VERSION 5.8 ;
BUSBITCHARS "[]" ;
DIVIDERCHAR "/" ;
UNITS
    DATABASE MICRONS 1000 ;
END UNITS

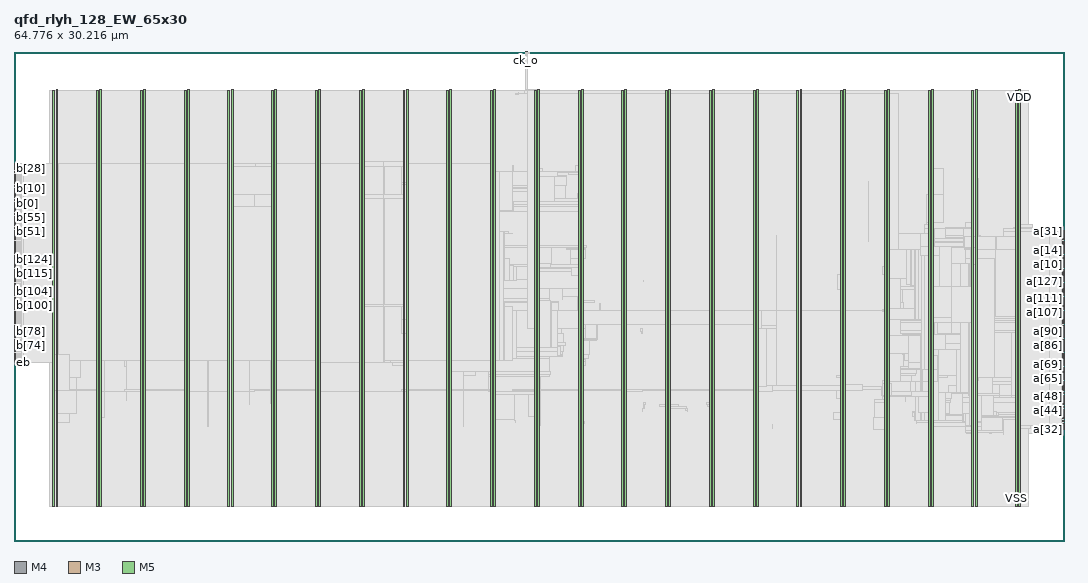
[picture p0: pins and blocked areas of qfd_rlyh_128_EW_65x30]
MACRO qfd_rlyh_128_EW_65x30
  FOREIGN qfd_rlyh_128_EW_65x30 0 0 ;
  CLASS BLOCK ;
  SIZE 64.776 BY 30.216 ;
  PIN a[0]
    DIRECTION INPUT ;
    USE SIGNAL ;
    PORT
      LAYER M4 ;
        RECT  64.692 16.08 64.776 16.104 ;
    END
  END a[0]
  PIN a[100]
    DIRECTION INPUT ;
    USE SIGNAL ;
    PORT
      LAYER M4 ;
        RECT  64.692 13.392 64.776 13.416 ;
    END
  END a[100]
  PIN a[101]
    DIRECTION INPUT ;
    USE SIGNAL ;
    PORT
      LAYER M4 ;
        RECT  64.692 13.488 64.776 13.512 ;
    END
  END a[101]
  PIN a[102]
    DIRECTION INPUT ;
    USE SIGNAL ;
    PORT
      LAYER M4 ;
        RECT  64.692 13.584 64.776 13.608 ;
    END
  END a[102]
  PIN a[103]
    DIRECTION INPUT ;
    USE SIGNAL ;
    PORT
      LAYER M4 ;
        RECT  64.692 13.68 64.776 13.704 ;
    END
  END a[103]
  PIN a[104]
    DIRECTION INPUT ;
    USE SIGNAL ;
    PORT
      LAYER M4 ;
        RECT  64.692 13.776 64.776 13.8 ;
    END
  END a[104]
  PIN a[105]
    DIRECTION INPUT ;
    USE SIGNAL ;
    PORT
      LAYER M4 ;
        RECT  64.692 13.872 64.776 13.896 ;
    END
  END a[105]
  PIN a[106]
    DIRECTION INPUT ;
    USE SIGNAL ;
    PORT
      LAYER M4 ;
        RECT  64.692 13.968 64.776 13.992 ;
    END
  END a[106]
  PIN a[107]
    DIRECTION INPUT ;
    USE SIGNAL ;
    PORT
      LAYER M4 ;
        RECT  64.692 14.064 64.776 14.088 ;
    END
  END a[107]
  PIN a[108]
    DIRECTION INPUT ;
    USE SIGNAL ;
    PORT
      LAYER M4 ;
        RECT  64.692 14.16 64.776 14.184 ;
    END
  END a[108]
  PIN a[109]
    DIRECTION INPUT ;
    USE SIGNAL ;
    PORT
      LAYER M4 ;
        RECT  64.692 14.256 64.776 14.28 ;
    END
  END a[109]
  PIN a[10]
    DIRECTION INPUT ;
    USE SIGNAL ;
    PORT
      LAYER M4 ;
        RECT  64.692 17.04 64.776 17.064 ;
    END
  END a[10]
  PIN a[110]
    DIRECTION INPUT ;
    USE SIGNAL ;
    PORT
      LAYER M4 ;
        RECT  64.692 14.352 64.776 14.376 ;
    END
  END a[110]
  PIN a[111]
    DIRECTION INPUT ;
    USE SIGNAL ;
    PORT
      LAYER M4 ;
        RECT  64.692 14.448 64.776 14.472 ;
    END
  END a[111]
  PIN a[112]
    DIRECTION INPUT ;
    USE SIGNAL ;
    PORT
      LAYER M4 ;
        RECT  64.692 14.544 64.776 14.568 ;
    END
  END a[112]
  PIN a[113]
    DIRECTION INPUT ;
    USE SIGNAL ;
    PORT
      LAYER M4 ;
        RECT  64.692 14.64 64.776 14.664 ;
    END
  END a[113]
  PIN a[114]
    DIRECTION INPUT ;
    USE SIGNAL ;
    PORT
      LAYER M4 ;
        RECT  64.692 14.736 64.776 14.76 ;
    END
  END a[114]
  PIN a[115]
    DIRECTION INPUT ;
    USE SIGNAL ;
    PORT
      LAYER M4 ;
        RECT  64.692 14.832 64.776 14.856 ;
    END
  END a[115]
  PIN a[116]
    DIRECTION INPUT ;
    USE SIGNAL ;
    PORT
      LAYER M4 ;
        RECT  64.692 14.928 64.776 14.952 ;
    END
  END a[116]
  PIN a[117]
    DIRECTION INPUT ;
    USE SIGNAL ;
    PORT
      LAYER M4 ;
        RECT  64.692 15.024 64.776 15.048 ;
    END
  END a[117]
  PIN a[118]
    DIRECTION INPUT ;
    USE SIGNAL ;
    PORT
      LAYER M4 ;
        RECT  64.692 15.12 64.776 15.144 ;
    END
  END a[118]
  PIN a[119]
    DIRECTION INPUT ;
    USE SIGNAL ;
    PORT
      LAYER M4 ;
        RECT  64.692 15.216 64.776 15.24 ;
    END
  END a[119]
  PIN a[11]
    DIRECTION INPUT ;
    USE SIGNAL ;
    PORT
      LAYER M4 ;
        RECT  64.692 17.136 64.776 17.16 ;
    END
  END a[11]
  PIN a[120]
    DIRECTION INPUT ;
    USE SIGNAL ;
    PORT
      LAYER M4 ;
        RECT  64.692 15.312 64.776 15.336 ;
    END
  END a[120]
  PIN a[121]
    DIRECTION INPUT ;
    USE SIGNAL ;
    PORT
      LAYER M4 ;
        RECT  64.692 15.408 64.776 15.432 ;
    END
  END a[121]
  PIN a[122]
    DIRECTION INPUT ;
    USE SIGNAL ;
    PORT
      LAYER M4 ;
        RECT  64.692 15.504 64.776 15.528 ;
    END
  END a[122]
  PIN a[123]
    DIRECTION INPUT ;
    USE SIGNAL ;
    PORT
      LAYER M4 ;
        RECT  64.692 15.6 64.776 15.624 ;
    END
  END a[123]
  PIN a[124]
    DIRECTION INPUT ;
    USE SIGNAL ;
    PORT
      LAYER M4 ;
        RECT  64.692 15.696 64.776 15.72 ;
    END
  END a[124]
  PIN a[125]
    DIRECTION INPUT ;
    USE SIGNAL ;
    PORT
      LAYER M4 ;
        RECT  64.692 15.792 64.776 15.816 ;
    END
  END a[125]
  PIN a[126]
    DIRECTION INPUT ;
    USE SIGNAL ;
    PORT
      LAYER M4 ;
        RECT  64.692 15.888 64.776 15.912 ;
    END
  END a[126]
  PIN a[127]
    DIRECTION INPUT ;
    USE SIGNAL ;
    PORT
      LAYER M4 ;
        RECT  64.692 15.984 64.776 16.008 ;
    END
  END a[127]
  PIN a[12]
    DIRECTION INPUT ;
    USE SIGNAL ;
    PORT
      LAYER M4 ;
        RECT  64.692 17.232 64.776 17.256 ;
    END
  END a[12]
  PIN a[13]
    DIRECTION INPUT ;
    USE SIGNAL ;
    PORT
      LAYER M4 ;
        RECT  64.692 17.328 64.776 17.352 ;
    END
  END a[13]
  PIN a[14]
    DIRECTION INPUT ;
    USE SIGNAL ;
    PORT
      LAYER M4 ;
        RECT  64.692 17.424 64.776 17.448 ;
    END
  END a[14]
  PIN a[15]
    DIRECTION INPUT ;
    USE SIGNAL ;
    PORT
      LAYER M4 ;
        RECT  64.692 17.52 64.776 17.544 ;
    END
  END a[15]
  PIN a[16]
    DIRECTION INPUT ;
    USE SIGNAL ;
    PORT
      LAYER M4 ;
        RECT  64.692 17.616 64.776 17.64 ;
    END
  END a[16]
  PIN a[17]
    DIRECTION INPUT ;
    USE SIGNAL ;
    PORT
      LAYER M4 ;
        RECT  64.692 17.712 64.776 17.736 ;
    END
  END a[17]
  PIN a[18]
    DIRECTION INPUT ;
    USE SIGNAL ;
    PORT
      LAYER M4 ;
        RECT  64.692 17.808 64.776 17.832 ;
    END
  END a[18]
  PIN a[19]
    DIRECTION INPUT ;
    USE SIGNAL ;
    PORT
      LAYER M4 ;
        RECT  64.692 17.904 64.776 17.928 ;
    END
  END a[19]
  PIN a[1]
    DIRECTION INPUT ;
    USE SIGNAL ;
    PORT
      LAYER M4 ;
        RECT  64.692 16.176 64.776 16.2 ;
    END
  END a[1]
  PIN a[20]
    DIRECTION INPUT ;
    USE SIGNAL ;
    PORT
      LAYER M4 ;
        RECT  64.692 18 64.776 18.024 ;
    END
  END a[20]
  PIN a[21]
    DIRECTION INPUT ;
    USE SIGNAL ;
    PORT
      LAYER M4 ;
        RECT  64.692 18.096 64.776 18.12 ;
    END
  END a[21]
  PIN a[22]
    DIRECTION INPUT ;
    USE SIGNAL ;
    PORT
      LAYER M4 ;
        RECT  64.692 18.192 64.776 18.216 ;
    END
  END a[22]
  PIN a[23]
    DIRECTION INPUT ;
    USE SIGNAL ;
    PORT
      LAYER M4 ;
        RECT  64.692 18.288 64.776 18.312 ;
    END
  END a[23]
  PIN a[24]
    DIRECTION INPUT ;
    USE SIGNAL ;
    PORT
      LAYER M4 ;
        RECT  64.692 18.384 64.776 18.408 ;
    END
  END a[24]
  PIN a[25]
    DIRECTION INPUT ;
    USE SIGNAL ;
    PORT
      LAYER M4 ;
        RECT  64.692 18.48 64.776 18.504 ;
    END
  END a[25]
  PIN a[26]
    DIRECTION INPUT ;
    USE SIGNAL ;
    PORT
      LAYER M4 ;
        RECT  64.692 18.576 64.776 18.6 ;
    END
  END a[26]
  PIN a[27]
    DIRECTION INPUT ;
    USE SIGNAL ;
    PORT
      LAYER M4 ;
        RECT  64.692 18.672 64.776 18.696 ;
    END
  END a[27]
  PIN a[28]
    DIRECTION INPUT ;
    USE SIGNAL ;
    PORT
      LAYER M4 ;
        RECT  64.692 18.768 64.776 18.792 ;
    END
  END a[28]
  PIN a[29]
    DIRECTION INPUT ;
    USE SIGNAL ;
    PORT
      LAYER M4 ;
        RECT  64.692 18.864 64.776 18.888 ;
    END
  END a[29]
  PIN a[2]
    DIRECTION INPUT ;
    USE SIGNAL ;
    PORT
      LAYER M4 ;
        RECT  64.692 16.272 64.776 16.296 ;
    END
  END a[2]
  PIN a[30]
    DIRECTION INPUT ;
    USE SIGNAL ;
    PORT
      LAYER M4 ;
        RECT  64.692 18.96 64.776 18.984 ;
    END
  END a[30]
  PIN a[31]
    DIRECTION INPUT ;
    USE SIGNAL ;
    PORT
      LAYER M4 ;
        RECT  64.692 19.056 64.776 19.08 ;
    END
  END a[31]
  PIN a[32]
    DIRECTION INPUT ;
    USE SIGNAL ;
    PORT
      LAYER M4 ;
        RECT  64.692 6.864 64.776 6.888 ;
    END
  END a[32]
  PIN a[33]
    DIRECTION INPUT ;
    USE SIGNAL ;
    PORT
      LAYER M4 ;
        RECT  64.692 6.96 64.776 6.984 ;
    END
  END a[33]
  PIN a[34]
    DIRECTION INPUT ;
    USE SIGNAL ;
    PORT
      LAYER M4 ;
        RECT  64.692 7.056 64.776 7.08 ;
    END
  END a[34]
  PIN a[35]
    DIRECTION INPUT ;
    USE SIGNAL ;
    PORT
      LAYER M4 ;
        RECT  64.692 7.152 64.776 7.176 ;
    END
  END a[35]
  PIN a[36]
    DIRECTION INPUT ;
    USE SIGNAL ;
    PORT
      LAYER M4 ;
        RECT  64.692 7.248 64.776 7.272 ;
    END
  END a[36]
  PIN a[37]
    DIRECTION INPUT ;
    USE SIGNAL ;
    PORT
      LAYER M4 ;
        RECT  64.692 7.344 64.776 7.368 ;
    END
  END a[37]
  PIN a[38]
    DIRECTION INPUT ;
    USE SIGNAL ;
    PORT
      LAYER M4 ;
        RECT  64.692 7.44 64.776 7.464 ;
    END
  END a[38]
  PIN a[39]
    DIRECTION INPUT ;
    USE SIGNAL ;
    PORT
      LAYER M4 ;
        RECT  64.692 7.536 64.776 7.56 ;
    END
  END a[39]
  PIN a[3]
    DIRECTION INPUT ;
    USE SIGNAL ;
    PORT
      LAYER M4 ;
        RECT  64.692 16.368 64.776 16.392 ;
    END
  END a[3]
  PIN a[40]
    DIRECTION INPUT ;
    USE SIGNAL ;
    PORT
      LAYER M4 ;
        RECT  64.692 7.632 64.776 7.656 ;
    END
  END a[40]
  PIN a[41]
    DIRECTION INPUT ;
    USE SIGNAL ;
    PORT
      LAYER M4 ;
        RECT  64.692 7.728 64.776 7.752 ;
    END
  END a[41]
  PIN a[42]
    DIRECTION INPUT ;
    USE SIGNAL ;
    PORT
      LAYER M4 ;
        RECT  64.692 7.824 64.776 7.848 ;
    END
  END a[42]
  PIN a[43]
    DIRECTION INPUT ;
    USE SIGNAL ;
    PORT
      LAYER M4 ;
        RECT  64.692 7.92 64.776 7.944 ;
    END
  END a[43]
  PIN a[44]
    DIRECTION INPUT ;
    USE SIGNAL ;
    PORT
      LAYER M4 ;
        RECT  64.692 8.016 64.776 8.04 ;
    END
  END a[44]
  PIN a[45]
    DIRECTION INPUT ;
    USE SIGNAL ;
    PORT
      LAYER M4 ;
        RECT  64.692 8.112 64.776 8.136 ;
    END
  END a[45]
  PIN a[46]
    DIRECTION INPUT ;
    USE SIGNAL ;
    PORT
      LAYER M4 ;
        RECT  64.692 8.208 64.776 8.232 ;
    END
  END a[46]
  PIN a[47]
    DIRECTION INPUT ;
    USE SIGNAL ;
    PORT
      LAYER M4 ;
        RECT  64.692 8.304 64.776 8.328 ;
    END
  END a[47]
  PIN a[48]
    DIRECTION INPUT ;
    USE SIGNAL ;
    PORT
      LAYER M4 ;
        RECT  64.692 8.4 64.776 8.424 ;
    END
  END a[48]
  PIN a[49]
    DIRECTION INPUT ;
    USE SIGNAL ;
    PORT
      LAYER M4 ;
        RECT  64.692 8.496 64.776 8.52 ;
    END
  END a[49]
  PIN a[4]
    DIRECTION INPUT ;
    USE SIGNAL ;
    PORT
      LAYER M4 ;
        RECT  64.692 16.464 64.776 16.488 ;
    END
  END a[4]
  PIN a[50]
    DIRECTION INPUT ;
    USE SIGNAL ;
    PORT
      LAYER M4 ;
        RECT  64.692 8.592 64.776 8.616 ;
    END
  END a[50]
  PIN a[51]
    DIRECTION INPUT ;
    USE SIGNAL ;
    PORT
      LAYER M4 ;
        RECT  64.692 8.688 64.776 8.712 ;
    END
  END a[51]
  PIN a[52]
    DIRECTION INPUT ;
    USE SIGNAL ;
    PORT
      LAYER M4 ;
        RECT  64.692 8.784 64.776 8.808 ;
    END
  END a[52]
  PIN a[53]
    DIRECTION INPUT ;
    USE SIGNAL ;
    PORT
      LAYER M4 ;
        RECT  64.692 8.88 64.776 8.904 ;
    END
  END a[53]
  PIN a[54]
    DIRECTION INPUT ;
    USE SIGNAL ;
    PORT
      LAYER M4 ;
        RECT  64.692 8.976 64.776 9 ;
    END
  END a[54]
  PIN a[55]
    DIRECTION INPUT ;
    USE SIGNAL ;
    PORT
      LAYER M4 ;
        RECT  64.692 9.072 64.776 9.096 ;
    END
  END a[55]
  PIN a[56]
    DIRECTION INPUT ;
    USE SIGNAL ;
    PORT
      LAYER M4 ;
        RECT  64.692 9.168 64.776 9.192 ;
    END
  END a[56]
  PIN a[57]
    DIRECTION INPUT ;
    USE SIGNAL ;
    PORT
      LAYER M4 ;
        RECT  64.692 9.264 64.776 9.288 ;
    END
  END a[57]
  PIN a[58]
    DIRECTION INPUT ;
    USE SIGNAL ;
    PORT
      LAYER M4 ;
        RECT  64.692 9.36 64.776 9.384 ;
    END
  END a[58]
  PIN a[59]
    DIRECTION INPUT ;
    USE SIGNAL ;
    PORT
      LAYER M4 ;
        RECT  64.692 9.456 64.776 9.48 ;
    END
  END a[59]
  PIN a[5]
    DIRECTION INPUT ;
    USE SIGNAL ;
    PORT
      LAYER M4 ;
        RECT  64.692 16.56 64.776 16.584 ;
    END
  END a[5]
  PIN a[60]
    DIRECTION INPUT ;
    USE SIGNAL ;
    PORT
      LAYER M4 ;
        RECT  64.692 9.552 64.776 9.576 ;
    END
  END a[60]
  PIN a[61]
    DIRECTION INPUT ;
    USE SIGNAL ;
    PORT
      LAYER M4 ;
        RECT  64.692 9.648 64.776 9.672 ;
    END
  END a[61]
  PIN a[62]
    DIRECTION INPUT ;
    USE SIGNAL ;
    PORT
      LAYER M4 ;
        RECT  64.692 9.744 64.776 9.768 ;
    END
  END a[62]
  PIN a[63]
    DIRECTION INPUT ;
    USE SIGNAL ;
    PORT
      LAYER M4 ;
        RECT  64.692 9.84 64.776 9.864 ;
    END
  END a[63]
  PIN a[64]
    DIRECTION INPUT ;
    USE SIGNAL ;
    PORT
      LAYER M4 ;
        RECT  64.692 9.936 64.776 9.96 ;
    END
  END a[64]
  PIN a[65]
    DIRECTION INPUT ;
    USE SIGNAL ;
    PORT
      LAYER M4 ;
        RECT  64.692 10.032 64.776 10.056 ;
    END
  END a[65]
  PIN a[66]
    DIRECTION INPUT ;
    USE SIGNAL ;
    PORT
      LAYER M4 ;
        RECT  64.692 10.128 64.776 10.152 ;
    END
  END a[66]
  PIN a[67]
    DIRECTION INPUT ;
    USE SIGNAL ;
    PORT
      LAYER M4 ;
        RECT  64.692 10.224 64.776 10.248 ;
    END
  END a[67]
  PIN a[68]
    DIRECTION INPUT ;
    USE SIGNAL ;
    PORT
      LAYER M4 ;
        RECT  64.692 10.32 64.776 10.344 ;
    END
  END a[68]
  PIN a[69]
    DIRECTION INPUT ;
    USE SIGNAL ;
    PORT
      LAYER M4 ;
        RECT  64.692 10.416 64.776 10.44 ;
    END
  END a[69]
  PIN a[6]
    DIRECTION INPUT ;
    USE SIGNAL ;
    PORT
      LAYER M4 ;
        RECT  64.692 16.656 64.776 16.68 ;
    END
  END a[6]
  PIN a[70]
    DIRECTION INPUT ;
    USE SIGNAL ;
    PORT
      LAYER M4 ;
        RECT  64.692 10.512 64.776 10.536 ;
    END
  END a[70]
  PIN a[71]
    DIRECTION INPUT ;
    USE SIGNAL ;
    PORT
      LAYER M4 ;
        RECT  64.692 10.608 64.776 10.632 ;
    END
  END a[71]
  PIN a[72]
    DIRECTION INPUT ;
    USE SIGNAL ;
    PORT
      LAYER M4 ;
        RECT  64.692 10.704 64.776 10.728 ;
    END
  END a[72]
  PIN a[73]
    DIRECTION INPUT ;
    USE SIGNAL ;
    PORT
      LAYER M4 ;
        RECT  64.692 10.8 64.776 10.824 ;
    END
  END a[73]
  PIN a[74]
    DIRECTION INPUT ;
    USE SIGNAL ;
    PORT
      LAYER M4 ;
        RECT  64.692 10.896 64.776 10.92 ;
    END
  END a[74]
  PIN a[75]
    DIRECTION INPUT ;
    USE SIGNAL ;
    PORT
      LAYER M4 ;
        RECT  64.692 10.992 64.776 11.016 ;
    END
  END a[75]
  PIN a[76]
    DIRECTION INPUT ;
    USE SIGNAL ;
    PORT
      LAYER M4 ;
        RECT  64.692 11.088 64.776 11.112 ;
    END
  END a[76]
  PIN a[77]
    DIRECTION INPUT ;
    USE SIGNAL ;
    PORT
      LAYER M4 ;
        RECT  64.692 11.184 64.776 11.208 ;
    END
  END a[77]
  PIN a[78]
    DIRECTION INPUT ;
    USE SIGNAL ;
    PORT
      LAYER M4 ;
        RECT  64.692 11.28 64.776 11.304 ;
    END
  END a[78]
  PIN a[79]
    DIRECTION INPUT ;
    USE SIGNAL ;
    PORT
      LAYER M4 ;
        RECT  64.692 11.376 64.776 11.4 ;
    END
  END a[79]
  PIN a[7]
    DIRECTION INPUT ;
    USE SIGNAL ;
    PORT
      LAYER M4 ;
        RECT  64.692 16.752 64.776 16.776 ;
    END
  END a[7]
  PIN a[80]
    DIRECTION INPUT ;
    USE SIGNAL ;
    PORT
      LAYER M4 ;
        RECT  64.692 11.472 64.776 11.496 ;
    END
  END a[80]
  PIN a[81]
    DIRECTION INPUT ;
    USE SIGNAL ;
    PORT
      LAYER M4 ;
        RECT  64.692 11.568 64.776 11.592 ;
    END
  END a[81]
  PIN a[82]
    DIRECTION INPUT ;
    USE SIGNAL ;
    PORT
      LAYER M4 ;
        RECT  64.692 11.664 64.776 11.688 ;
    END
  END a[82]
  PIN a[83]
    DIRECTION INPUT ;
    USE SIGNAL ;
    PORT
      LAYER M4 ;
        RECT  64.692 11.76 64.776 11.784 ;
    END
  END a[83]
  PIN a[84]
    DIRECTION INPUT ;
    USE SIGNAL ;
    PORT
      LAYER M4 ;
        RECT  64.692 11.856 64.776 11.88 ;
    END
  END a[84]
  PIN a[85]
    DIRECTION INPUT ;
    USE SIGNAL ;
    PORT
      LAYER M4 ;
        RECT  64.692 11.952 64.776 11.976 ;
    END
  END a[85]
  PIN a[86]
    DIRECTION INPUT ;
    USE SIGNAL ;
    PORT
      LAYER M4 ;
        RECT  64.692 12.048 64.776 12.072 ;
    END
  END a[86]
  PIN a[87]
    DIRECTION INPUT ;
    USE SIGNAL ;
    PORT
      LAYER M4 ;
        RECT  64.692 12.144 64.776 12.168 ;
    END
  END a[87]
  PIN a[88]
    DIRECTION INPUT ;
    USE SIGNAL ;
    PORT
      LAYER M4 ;
        RECT  64.692 12.24 64.776 12.264 ;
    END
  END a[88]
  PIN a[89]
    DIRECTION INPUT ;
    USE SIGNAL ;
    PORT
      LAYER M4 ;
        RECT  64.692 12.336 64.776 12.36 ;
    END
  END a[89]
  PIN a[8]
    DIRECTION INPUT ;
    USE SIGNAL ;
    PORT
      LAYER M4 ;
        RECT  64.692 16.848 64.776 16.872 ;
    END
  END a[8]
  PIN a[90]
    DIRECTION INPUT ;
    USE SIGNAL ;
    PORT
      LAYER M4 ;
        RECT  64.692 12.432 64.776 12.456 ;
    END
  END a[90]
  PIN a[91]
    DIRECTION INPUT ;
    USE SIGNAL ;
    PORT
      LAYER M4 ;
        RECT  64.692 12.528 64.776 12.552 ;
    END
  END a[91]
  PIN a[92]
    DIRECTION INPUT ;
    USE SIGNAL ;
    PORT
      LAYER M4 ;
        RECT  64.692 12.624 64.776 12.648 ;
    END
  END a[92]
  PIN a[93]
    DIRECTION INPUT ;
    USE SIGNAL ;
    PORT
      LAYER M4 ;
        RECT  64.692 12.72 64.776 12.744 ;
    END
  END a[93]
  PIN a[94]
    DIRECTION INPUT ;
    USE SIGNAL ;
    PORT
      LAYER M4 ;
        RECT  64.692 12.816 64.776 12.84 ;
    END
  END a[94]
  PIN a[95]
    DIRECTION INPUT ;
    USE SIGNAL ;
    PORT
      LAYER M4 ;
        RECT  64.692 12.912 64.776 12.936 ;
    END
  END a[95]
  PIN a[96]
    DIRECTION INPUT ;
    USE SIGNAL ;
    PORT
      LAYER M4 ;
        RECT  64.692 13.008 64.776 13.032 ;
    END
  END a[96]
  PIN a[97]
    DIRECTION INPUT ;
    USE SIGNAL ;
    PORT
      LAYER M4 ;
        RECT  64.692 13.104 64.776 13.128 ;
    END
  END a[97]
  PIN a[98]
    DIRECTION INPUT ;
    USE SIGNAL ;
    PORT
      LAYER M4 ;
        RECT  64.692 13.2 64.776 13.224 ;
    END
  END a[98]
  PIN a[99]
    DIRECTION INPUT ;
    USE SIGNAL ;
    PORT
      LAYER M4 ;
        RECT  64.692 13.296 64.776 13.32 ;
    END
  END a[99]
  PIN a[9]
    DIRECTION INPUT ;
    USE SIGNAL ;
    PORT
      LAYER M4 ;
        RECT  64.692 16.944 64.776 16.968 ;
    END
  END a[9]
  PIN b[0]
    DIRECTION OUTPUT ;
    USE SIGNAL ;
    PORT
      LAYER M4 ;
        RECT  0 20.304 0.084 20.328 ;
    END
  END b[0]
  PIN b[100]
    DIRECTION OUTPUT ;
    USE SIGNAL ;
    PORT
      LAYER M4 ;
        RECT  0 14.544 0.084 14.568 ;
    END
  END b[100]
  PIN b[101]
    DIRECTION OUTPUT ;
    USE SIGNAL ;
    PORT
      LAYER M4 ;
        RECT  0 14.64 0.084 14.664 ;
    END
  END b[101]
  PIN b[102]
    DIRECTION OUTPUT ;
    USE SIGNAL ;
    PORT
      LAYER M4 ;
        RECT  0 14.736 0.084 14.76 ;
    END
  END b[102]
  PIN b[103]
    DIRECTION OUTPUT ;
    USE SIGNAL ;
    PORT
      LAYER M4 ;
        RECT  0 14.832 0.084 14.856 ;
    END
  END b[103]
  PIN b[104]
    DIRECTION OUTPUT ;
    USE SIGNAL ;
    PORT
      LAYER M4 ;
        RECT  0 14.928 0.084 14.952 ;
    END
  END b[104]
  PIN b[105]
    DIRECTION OUTPUT ;
    USE SIGNAL ;
    PORT
      LAYER M4 ;
        RECT  0 15.024 0.084 15.048 ;
    END
  END b[105]
  PIN b[106]
    DIRECTION OUTPUT ;
    USE SIGNAL ;
    PORT
      LAYER M4 ;
        RECT  0 15.12 0.084 15.144 ;
    END
  END b[106]
  PIN b[107]
    DIRECTION OUTPUT ;
    USE SIGNAL ;
    PORT
      LAYER M4 ;
        RECT  0 15.216 0.084 15.24 ;
    END
  END b[107]
  PIN b[108]
    DIRECTION OUTPUT ;
    USE SIGNAL ;
    PORT
      LAYER M4 ;
        RECT  0 15.312 0.084 15.336 ;
    END
  END b[108]
  PIN b[109]
    DIRECTION OUTPUT ;
    USE SIGNAL ;
    PORT
      LAYER M4 ;
        RECT  0 15.408 0.084 15.432 ;
    END
  END b[109]
  PIN b[10]
    DIRECTION OUTPUT ;
    USE SIGNAL ;
    PORT
      LAYER M4 ;
        RECT  0 21.264 0.084 21.288 ;
    END
  END b[10]
  PIN b[110]
    DIRECTION OUTPUT ;
    USE SIGNAL ;
    PORT
      LAYER M4 ;
        RECT  0 15.504 0.084 15.528 ;
    END
  END b[110]
  PIN b[111]
    DIRECTION OUTPUT ;
    USE SIGNAL ;
    PORT
      LAYER M4 ;
        RECT  0 15.6 0.084 15.624 ;
    END
  END b[111]
  PIN b[112]
    DIRECTION OUTPUT ;
    USE SIGNAL ;
    PORT
      LAYER M4 ;
        RECT  0 15.696 0.084 15.72 ;
    END
  END b[112]
  PIN b[113]
    DIRECTION OUTPUT ;
    USE SIGNAL ;
    PORT
      LAYER M4 ;
        RECT  0 15.792 0.084 15.816 ;
    END
  END b[113]
  PIN b[114]
    DIRECTION OUTPUT ;
    USE SIGNAL ;
    PORT
      LAYER M4 ;
        RECT  0 15.888 0.084 15.912 ;
    END
  END b[114]
  PIN b[115]
    DIRECTION OUTPUT ;
    USE SIGNAL ;
    PORT
      LAYER M4 ;
        RECT  0 15.984 0.084 16.008 ;
    END
  END b[115]
  PIN b[116]
    DIRECTION OUTPUT ;
    USE SIGNAL ;
    PORT
      LAYER M4 ;
        RECT  0 16.08 0.084 16.104 ;
    END
  END b[116]
  PIN b[117]
    DIRECTION OUTPUT ;
    USE SIGNAL ;
    PORT
      LAYER M4 ;
        RECT  0 16.176 0.084 16.2 ;
    END
  END b[117]
  PIN b[118]
    DIRECTION OUTPUT ;
    USE SIGNAL ;
    PORT
      LAYER M4 ;
        RECT  0 16.272 0.084 16.296 ;
    END
  END b[118]
  PIN b[119]
    DIRECTION OUTPUT ;
    USE SIGNAL ;
    PORT
      LAYER M4 ;
        RECT  0 16.368 0.084 16.392 ;
    END
  END b[119]
  PIN b[11]
    DIRECTION OUTPUT ;
    USE SIGNAL ;
    PORT
      LAYER M4 ;
        RECT  0 21.36 0.084 21.384 ;
    END
  END b[11]
  PIN b[120]
    DIRECTION OUTPUT ;
    USE SIGNAL ;
    PORT
      LAYER M4 ;
        RECT  0 16.464 0.084 16.488 ;
    END
  END b[120]
  PIN b[121]
    DIRECTION OUTPUT ;
    USE SIGNAL ;
    PORT
      LAYER M4 ;
        RECT  0 16.56 0.084 16.584 ;
    END
  END b[121]
  PIN b[122]
    DIRECTION OUTPUT ;
    USE SIGNAL ;
    PORT
      LAYER M4 ;
        RECT  0 16.656 0.084 16.68 ;
    END
  END b[122]
  PIN b[123]
    DIRECTION OUTPUT ;
    USE SIGNAL ;
    PORT
      LAYER M4 ;
        RECT  0 16.752 0.084 16.776 ;
    END
  END b[123]
  PIN b[124]
    DIRECTION OUTPUT ;
    USE SIGNAL ;
    PORT
      LAYER M4 ;
        RECT  0 16.848 0.084 16.872 ;
    END
  END b[124]
  PIN b[125]
    DIRECTION OUTPUT ;
    USE SIGNAL ;
    PORT
      LAYER M4 ;
        RECT  0 16.944 0.084 16.968 ;
    END
  END b[125]
  PIN b[126]
    DIRECTION OUTPUT ;
    USE SIGNAL ;
    PORT
      LAYER M4 ;
        RECT  0 17.04 0.084 17.064 ;
    END
  END b[126]
  PIN b[127]
    DIRECTION OUTPUT ;
    USE SIGNAL ;
    PORT
      LAYER M4 ;
        RECT  0 17.136 0.084 17.16 ;
    END
  END b[127]
  PIN b[12]
    DIRECTION OUTPUT ;
    USE SIGNAL ;
    PORT
      LAYER M4 ;
        RECT  0 21.456 0.084 21.48 ;
    END
  END b[12]
  PIN b[13]
    DIRECTION OUTPUT ;
    USE SIGNAL ;
    PORT
      LAYER M4 ;
        RECT  0 21.552 0.084 21.576 ;
    END
  END b[13]
  PIN b[14]
    DIRECTION OUTPUT ;
    USE SIGNAL ;
    PORT
      LAYER M4 ;
        RECT  0 21.648 0.084 21.672 ;
    END
  END b[14]
  PIN b[15]
    DIRECTION OUTPUT ;
    USE SIGNAL ;
    PORT
      LAYER M4 ;
        RECT  0 21.744 0.084 21.768 ;
    END
  END b[15]
  PIN b[16]
    DIRECTION OUTPUT ;
    USE SIGNAL ;
    PORT
      LAYER M4 ;
        RECT  0 21.84 0.084 21.864 ;
    END
  END b[16]
  PIN b[17]
    DIRECTION OUTPUT ;
    USE SIGNAL ;
    PORT
      LAYER M4 ;
        RECT  0 21.936 0.084 21.96 ;
    END
  END b[17]
  PIN b[18]
    DIRECTION OUTPUT ;
    USE SIGNAL ;
    PORT
      LAYER M4 ;
        RECT  0 22.032 0.084 22.056 ;
    END
  END b[18]
  PIN b[19]
    DIRECTION OUTPUT ;
    USE SIGNAL ;
    PORT
      LAYER M4 ;
        RECT  0 22.128 0.084 22.152 ;
    END
  END b[19]
  PIN b[1]
    DIRECTION OUTPUT ;
    USE SIGNAL ;
    PORT
      LAYER M4 ;
        RECT  0 20.4 0.084 20.424 ;
    END
  END b[1]
  PIN b[20]
    DIRECTION OUTPUT ;
    USE SIGNAL ;
    PORT
      LAYER M4 ;
        RECT  0 22.224 0.084 22.248 ;
    END
  END b[20]
  PIN b[21]
    DIRECTION OUTPUT ;
    USE SIGNAL ;
    PORT
      LAYER M4 ;
        RECT  0 22.32 0.084 22.344 ;
    END
  END b[21]
  PIN b[22]
    DIRECTION OUTPUT ;
    USE SIGNAL ;
    PORT
      LAYER M4 ;
        RECT  0 22.416 0.084 22.44 ;
    END
  END b[22]
  PIN b[23]
    DIRECTION OUTPUT ;
    USE SIGNAL ;
    PORT
      LAYER M4 ;
        RECT  0 22.512 0.084 22.536 ;
    END
  END b[23]
  PIN b[24]
    DIRECTION OUTPUT ;
    USE SIGNAL ;
    PORT
      LAYER M4 ;
        RECT  0 22.608 0.084 22.632 ;
    END
  END b[24]
  PIN b[25]
    DIRECTION OUTPUT ;
    USE SIGNAL ;
    PORT
      LAYER M4 ;
        RECT  0 22.704 0.084 22.728 ;
    END
  END b[25]
  PIN b[26]
    DIRECTION OUTPUT ;
    USE SIGNAL ;
    PORT
      LAYER M4 ;
        RECT  0 22.8 0.084 22.824 ;
    END
  END b[26]
  PIN b[27]
    DIRECTION OUTPUT ;
    USE SIGNAL ;
    PORT
      LAYER M4 ;
        RECT  0 22.896 0.084 22.92 ;
    END
  END b[27]
  PIN b[28]
    DIRECTION OUTPUT ;
    USE SIGNAL ;
    PORT
      LAYER M4 ;
        RECT  0 22.992 0.084 23.016 ;
    END
  END b[28]
  PIN b[29]
    DIRECTION OUTPUT ;
    USE SIGNAL ;
    PORT
      LAYER M4 ;
        RECT  0 23.088 0.084 23.112 ;
    END
  END b[29]
  PIN b[2]
    DIRECTION OUTPUT ;
    USE SIGNAL ;
    PORT
      LAYER M4 ;
        RECT  0 20.496 0.084 20.52 ;
    END
  END b[2]
  PIN b[30]
    DIRECTION OUTPUT ;
    USE SIGNAL ;
    PORT
      LAYER M4 ;
        RECT  0 23.184 0.084 23.208 ;
    END
  END b[30]
  PIN b[31]
    DIRECTION OUTPUT ;
    USE SIGNAL ;
    PORT
      LAYER M4 ;
        RECT  0 23.28 0.084 23.304 ;
    END
  END b[31]
  PIN b[32]
    DIRECTION OUTPUT ;
    USE SIGNAL ;
    PORT
      LAYER M4 ;
        RECT  0 17.232 0.084 17.256 ;
    END
  END b[32]
  PIN b[33]
    DIRECTION OUTPUT ;
    USE SIGNAL ;
    PORT
      LAYER M4 ;
        RECT  0 17.328 0.084 17.352 ;
    END
  END b[33]
  PIN b[34]
    DIRECTION OUTPUT ;
    USE SIGNAL ;
    PORT
      LAYER M4 ;
        RECT  0 17.424 0.084 17.448 ;
    END
  END b[34]
  PIN b[35]
    DIRECTION OUTPUT ;
    USE SIGNAL ;
    PORT
      LAYER M4 ;
        RECT  0 17.52 0.084 17.544 ;
    END
  END b[35]
  PIN b[36]
    DIRECTION OUTPUT ;
    USE SIGNAL ;
    PORT
      LAYER M4 ;
        RECT  0 17.616 0.084 17.64 ;
    END
  END b[36]
  PIN b[37]
    DIRECTION OUTPUT ;
    USE SIGNAL ;
    PORT
      LAYER M4 ;
        RECT  0 17.712 0.084 17.736 ;
    END
  END b[37]
  PIN b[38]
    DIRECTION OUTPUT ;
    USE SIGNAL ;
    PORT
      LAYER M4 ;
        RECT  0 17.808 0.084 17.832 ;
    END
  END b[38]
  PIN b[39]
    DIRECTION OUTPUT ;
    USE SIGNAL ;
    PORT
      LAYER M4 ;
        RECT  0 17.904 0.084 17.928 ;
    END
  END b[39]
  PIN b[3]
    DIRECTION OUTPUT ;
    USE SIGNAL ;
    PORT
      LAYER M4 ;
        RECT  0 20.592 0.084 20.616 ;
    END
  END b[3]
  PIN b[40]
    DIRECTION OUTPUT ;
    USE SIGNAL ;
    PORT
      LAYER M4 ;
        RECT  0 18 0.084 18.024 ;
    END
  END b[40]
  PIN b[41]
    DIRECTION OUTPUT ;
    USE SIGNAL ;
    PORT
      LAYER M4 ;
        RECT  0 18.096 0.084 18.12 ;
    END
  END b[41]
  PIN b[42]
    DIRECTION OUTPUT ;
    USE SIGNAL ;
    PORT
      LAYER M4 ;
        RECT  0 18.192 0.084 18.216 ;
    END
  END b[42]
  PIN b[43]
    DIRECTION OUTPUT ;
    USE SIGNAL ;
    PORT
      LAYER M4 ;
        RECT  0 18.288 0.084 18.312 ;
    END
  END b[43]
  PIN b[44]
    DIRECTION OUTPUT ;
    USE SIGNAL ;
    PORT
      LAYER M4 ;
        RECT  0 18.384 0.084 18.408 ;
    END
  END b[44]
  PIN b[45]
    DIRECTION OUTPUT ;
    USE SIGNAL ;
    PORT
      LAYER M4 ;
        RECT  0 18.48 0.084 18.504 ;
    END
  END b[45]
  PIN b[46]
    DIRECTION OUTPUT ;
    USE SIGNAL ;
    PORT
      LAYER M4 ;
        RECT  0 18.576 0.084 18.6 ;
    END
  END b[46]
  PIN b[47]
    DIRECTION OUTPUT ;
    USE SIGNAL ;
    PORT
      LAYER M4 ;
        RECT  0 18.672 0.084 18.696 ;
    END
  END b[47]
  PIN b[48]
    DIRECTION OUTPUT ;
    USE SIGNAL ;
    PORT
      LAYER M4 ;
        RECT  0 18.768 0.084 18.792 ;
    END
  END b[48]
  PIN b[49]
    DIRECTION OUTPUT ;
    USE SIGNAL ;
    PORT
      LAYER M4 ;
        RECT  0 18.864 0.084 18.888 ;
    END
  END b[49]
  PIN b[4]
    DIRECTION OUTPUT ;
    USE SIGNAL ;
    PORT
      LAYER M4 ;
        RECT  0 20.688 0.084 20.712 ;
    END
  END b[4]
  PIN b[50]
    DIRECTION OUTPUT ;
    USE SIGNAL ;
    PORT
      LAYER M4 ;
        RECT  0 18.96 0.084 18.984 ;
    END
  END b[50]
  PIN b[51]
    DIRECTION OUTPUT ;
    USE SIGNAL ;
    PORT
      LAYER M4 ;
        RECT  0 19.056 0.084 19.08 ;
    END
  END b[51]
  PIN b[52]
    DIRECTION OUTPUT ;
    USE SIGNAL ;
    PORT
      LAYER M4 ;
        RECT  0 19.152 0.084 19.176 ;
    END
  END b[52]
  PIN b[53]
    DIRECTION OUTPUT ;
    USE SIGNAL ;
    PORT
      LAYER M4 ;
        RECT  0 19.248 0.084 19.272 ;
    END
  END b[53]
  PIN b[54]
    DIRECTION OUTPUT ;
    USE SIGNAL ;
    PORT
      LAYER M4 ;
        RECT  0 19.344 0.084 19.368 ;
    END
  END b[54]
  PIN b[55]
    DIRECTION OUTPUT ;
    USE SIGNAL ;
    PORT
      LAYER M4 ;
        RECT  0 19.44 0.084 19.464 ;
    END
  END b[55]
  PIN b[56]
    DIRECTION OUTPUT ;
    USE SIGNAL ;
    PORT
      LAYER M4 ;
        RECT  0 19.536 0.084 19.56 ;
    END
  END b[56]
  PIN b[57]
    DIRECTION OUTPUT ;
    USE SIGNAL ;
    PORT
      LAYER M4 ;
        RECT  0 19.632 0.084 19.656 ;
    END
  END b[57]
  PIN b[58]
    DIRECTION OUTPUT ;
    USE SIGNAL ;
    PORT
      LAYER M4 ;
        RECT  0 19.728 0.084 19.752 ;
    END
  END b[58]
  PIN b[59]
    DIRECTION OUTPUT ;
    USE SIGNAL ;
    PORT
      LAYER M4 ;
        RECT  0 19.824 0.084 19.848 ;
    END
  END b[59]
  PIN b[5]
    DIRECTION OUTPUT ;
    USE SIGNAL ;
    PORT
      LAYER M4 ;
        RECT  0 20.784 0.084 20.808 ;
    END
  END b[5]
  PIN b[60]
    DIRECTION OUTPUT ;
    USE SIGNAL ;
    PORT
      LAYER M4 ;
        RECT  0 19.92 0.084 19.944 ;
    END
  END b[60]
  PIN b[61]
    DIRECTION OUTPUT ;
    USE SIGNAL ;
    PORT
      LAYER M4 ;
        RECT  0 20.016 0.084 20.04 ;
    END
  END b[61]
  PIN b[62]
    DIRECTION OUTPUT ;
    USE SIGNAL ;
    PORT
      LAYER M4 ;
        RECT  0 20.112 0.084 20.136 ;
    END
  END b[62]
  PIN b[63]
    DIRECTION OUTPUT ;
    USE SIGNAL ;
    PORT
      LAYER M4 ;
        RECT  0 20.208 0.084 20.232 ;
    END
  END b[63]
  PIN b[64]
    DIRECTION OUTPUT ;
    USE SIGNAL ;
    PORT
      LAYER M4 ;
        RECT  0 11.088 0.084 11.112 ;
    END
  END b[64]
  PIN b[65]
    DIRECTION OUTPUT ;
    USE SIGNAL ;
    PORT
      LAYER M4 ;
        RECT  0 11.184 0.084 11.208 ;
    END
  END b[65]
  PIN b[66]
    DIRECTION OUTPUT ;
    USE SIGNAL ;
    PORT
      LAYER M4 ;
        RECT  0 11.28 0.084 11.304 ;
    END
  END b[66]
  PIN b[67]
    DIRECTION OUTPUT ;
    USE SIGNAL ;
    PORT
      LAYER M4 ;
        RECT  0 11.376 0.084 11.4 ;
    END
  END b[67]
  PIN b[68]
    DIRECTION OUTPUT ;
    USE SIGNAL ;
    PORT
      LAYER M4 ;
        RECT  0 11.472 0.084 11.496 ;
    END
  END b[68]
  PIN b[69]
    DIRECTION OUTPUT ;
    USE SIGNAL ;
    PORT
      LAYER M4 ;
        RECT  0 11.568 0.084 11.592 ;
    END
  END b[69]
  PIN b[6]
    DIRECTION OUTPUT ;
    USE SIGNAL ;
    PORT
      LAYER M4 ;
        RECT  0 20.88 0.084 20.904 ;
    END
  END b[6]
  PIN b[70]
    DIRECTION OUTPUT ;
    USE SIGNAL ;
    PORT
      LAYER M4 ;
        RECT  0 11.664 0.084 11.688 ;
    END
  END b[70]
  PIN b[71]
    DIRECTION OUTPUT ;
    USE SIGNAL ;
    PORT
      LAYER M4 ;
        RECT  0 11.76 0.084 11.784 ;
    END
  END b[71]
  PIN b[72]
    DIRECTION OUTPUT ;
    USE SIGNAL ;
    PORT
      LAYER M4 ;
        RECT  0 11.856 0.084 11.88 ;
    END
  END b[72]
  PIN b[73]
    DIRECTION OUTPUT ;
    USE SIGNAL ;
    PORT
      LAYER M4 ;
        RECT  0 11.952 0.084 11.976 ;
    END
  END b[73]
  PIN b[74]
    DIRECTION OUTPUT ;
    USE SIGNAL ;
    PORT
      LAYER M4 ;
        RECT  0 12.048 0.084 12.072 ;
    END
  END b[74]
  PIN b[75]
    DIRECTION OUTPUT ;
    USE SIGNAL ;
    PORT
      LAYER M4 ;
        RECT  0 12.144 0.084 12.168 ;
    END
  END b[75]
  PIN b[76]
    DIRECTION OUTPUT ;
    USE SIGNAL ;
    PORT
      LAYER M4 ;
        RECT  0 12.24 0.084 12.264 ;
    END
  END b[76]
  PIN b[77]
    DIRECTION OUTPUT ;
    USE SIGNAL ;
    PORT
      LAYER M4 ;
        RECT  0 12.336 0.084 12.36 ;
    END
  END b[77]
  PIN b[78]
    DIRECTION OUTPUT ;
    USE SIGNAL ;
    PORT
      LAYER M4 ;
        RECT  0 12.432 0.084 12.456 ;
    END
  END b[78]
  PIN b[79]
    DIRECTION OUTPUT ;
    USE SIGNAL ;
    PORT
      LAYER M4 ;
        RECT  0 12.528 0.084 12.552 ;
    END
  END b[79]
  PIN b[7]
    DIRECTION OUTPUT ;
    USE SIGNAL ;
    PORT
      LAYER M4 ;
        RECT  0 20.976 0.084 21 ;
    END
  END b[7]
  PIN b[80]
    DIRECTION OUTPUT ;
    USE SIGNAL ;
    PORT
      LAYER M4 ;
        RECT  0 12.624 0.084 12.648 ;
    END
  END b[80]
  PIN b[81]
    DIRECTION OUTPUT ;
    USE SIGNAL ;
    PORT
      LAYER M4 ;
        RECT  0 12.72 0.084 12.744 ;
    END
  END b[81]
  PIN b[82]
    DIRECTION OUTPUT ;
    USE SIGNAL ;
    PORT
      LAYER M4 ;
        RECT  0 12.816 0.084 12.84 ;
    END
  END b[82]
  PIN b[83]
    DIRECTION OUTPUT ;
    USE SIGNAL ;
    PORT
      LAYER M4 ;
        RECT  0 12.912 0.084 12.936 ;
    END
  END b[83]
  PIN b[84]
    DIRECTION OUTPUT ;
    USE SIGNAL ;
    PORT
      LAYER M4 ;
        RECT  0 13.008 0.084 13.032 ;
    END
  END b[84]
  PIN b[85]
    DIRECTION OUTPUT ;
    USE SIGNAL ;
    PORT
      LAYER M4 ;
        RECT  0 13.104 0.084 13.128 ;
    END
  END b[85]
  PIN b[86]
    DIRECTION OUTPUT ;
    USE SIGNAL ;
    PORT
      LAYER M4 ;
        RECT  0 13.2 0.084 13.224 ;
    END
  END b[86]
  PIN b[87]
    DIRECTION OUTPUT ;
    USE SIGNAL ;
    PORT
      LAYER M4 ;
        RECT  0 13.296 0.084 13.32 ;
    END
  END b[87]
  PIN b[88]
    DIRECTION OUTPUT ;
    USE SIGNAL ;
    PORT
      LAYER M4 ;
        RECT  0 13.392 0.084 13.416 ;
    END
  END b[88]
  PIN b[89]
    DIRECTION OUTPUT ;
    USE SIGNAL ;
    PORT
      LAYER M4 ;
        RECT  0 13.488 0.084 13.512 ;
    END
  END b[89]
  PIN b[8]
    DIRECTION OUTPUT ;
    USE SIGNAL ;
    PORT
      LAYER M4 ;
        RECT  0 21.072 0.084 21.096 ;
    END
  END b[8]
  PIN b[90]
    DIRECTION OUTPUT ;
    USE SIGNAL ;
    PORT
      LAYER M4 ;
        RECT  0 13.584 0.084 13.608 ;
    END
  END b[90]
  PIN b[91]
    DIRECTION OUTPUT ;
    USE SIGNAL ;
    PORT
      LAYER M4 ;
        RECT  0 13.68 0.084 13.704 ;
    END
  END b[91]
  PIN b[92]
    DIRECTION OUTPUT ;
    USE SIGNAL ;
    PORT
      LAYER M4 ;
        RECT  0 13.776 0.084 13.8 ;
    END
  END b[92]
  PIN b[93]
    DIRECTION OUTPUT ;
    USE SIGNAL ;
    PORT
      LAYER M4 ;
        RECT  0 13.872 0.084 13.896 ;
    END
  END b[93]
  PIN b[94]
    DIRECTION OUTPUT ;
    USE SIGNAL ;
    PORT
      LAYER M4 ;
        RECT  0 13.968 0.084 13.992 ;
    END
  END b[94]
  PIN b[95]
    DIRECTION OUTPUT ;
    USE SIGNAL ;
    PORT
      LAYER M4 ;
        RECT  0 14.064 0.084 14.088 ;
    END
  END b[95]
  PIN b[96]
    DIRECTION OUTPUT ;
    USE SIGNAL ;
    PORT
      LAYER M4 ;
        RECT  0 14.16 0.084 14.184 ;
    END
  END b[96]
  PIN b[97]
    DIRECTION OUTPUT ;
    USE SIGNAL ;
    PORT
      LAYER M4 ;
        RECT  0 14.256 0.084 14.28 ;
    END
  END b[97]
  PIN b[98]
    DIRECTION OUTPUT ;
    USE SIGNAL ;
    PORT
      LAYER M4 ;
        RECT  0 14.352 0.084 14.376 ;
    END
  END b[98]
  PIN b[99]
    DIRECTION OUTPUT ;
    USE SIGNAL ;
    PORT
      LAYER M4 ;
        RECT  0 14.448 0.084 14.472 ;
    END
  END b[99]
  PIN b[9]
    DIRECTION OUTPUT ;
    USE SIGNAL ;
    PORT
      LAYER M4 ;
        RECT  0 21.168 0.084 21.192 ;
    END
  END b[9]
  PIN ck_o
    DIRECTION OUTPUT ;
    USE SIGNAL ;
    PORT
      LAYER M3 ;
        RECT  31.572 30.179 31.59 30.216 ;
    END
  END ck_o
  PIN ckf
    DIRECTION INPUT ;
    USE SIGNAL ;
    PORT
      LAYER M3 ;
        RECT  31.644 30.179 31.662 30.216 ;
    END
  END ckf
  PIN ea
    DIRECTION INPUT ;
    USE SIGNAL ;
    PORT
      LAYER M4 ;
        RECT  64.692 19.152 64.776 19.176 ;
    END
  END ea
  PIN eb
    DIRECTION OUTPUT ;
    USE SIGNAL ;
    PORT
      LAYER M4 ;
        RECT  0 10.992 0.084 11.016 ;
    END
  END eb
  PIN VDD
    DIRECTION INOUT ;
    USE POWER ;
    PORT
      LAYER M5 ;
        RECT  61.992 2.151 62.112 27.833 ;
        RECT  59.292 2.151 59.412 27.833 ;
        RECT  56.592 2.151 56.712 27.833 ;
        RECT  53.892 2.151 54.012 27.833 ;
        RECT  51.192 2.151 51.312 27.833 ;
        RECT  48.492 2.151 48.612 27.833 ;
        RECT  45.792 2.151 45.912 27.833 ;
        RECT  43.092 2.151 43.212 27.833 ;
        RECT  40.392 2.151 40.512 27.833 ;
        RECT  37.692 2.151 37.812 27.833 ;
        RECT  34.992 2.151 35.112 27.833 ;
        RECT  32.292 2.151 32.412 27.833 ;
        RECT  29.592 2.151 29.712 27.833 ;
        RECT  26.892 2.151 27.012 27.833 ;
        RECT  24.192 2.151 24.312 27.833 ;
        RECT  21.492 2.151 21.612 27.833 ;
        RECT  18.792 2.151 18.912 27.833 ;
        RECT  16.092 2.151 16.212 27.833 ;
        RECT  13.392 2.151 13.512 27.833 ;
        RECT  10.692 2.151 10.812 27.833 ;
        RECT  7.992 2.151 8.112 27.833 ;
        RECT  5.292 2.151 5.412 27.833 ;
        RECT  2.592 2.151 2.712 27.833 ;
    END
  END VDD
  PIN VSS
    DIRECTION INOUT ;
    USE GROUND ;
    PORT
      LAYER M5 ;
        RECT  61.8 2.137 61.92 27.819 ;
        RECT  59.1 2.137 59.22 27.819 ;
        RECT  56.4 2.137 56.52 27.819 ;
        RECT  53.7 2.137 53.82 27.819 ;
        RECT  51 2.137 51.12 27.819 ;
        RECT  48.3 2.137 48.42 27.819 ;
        RECT  45.6 2.137 45.72 27.819 ;
        RECT  42.9 2.137 43.02 27.819 ;
        RECT  40.2 2.137 40.32 27.819 ;
        RECT  37.5 2.137 37.62 27.819 ;
        RECT  34.8 2.137 34.92 27.819 ;
        RECT  32.1 2.137 32.22 27.819 ;
        RECT  29.4 2.137 29.52 27.819 ;
        RECT  26.7 2.137 26.82 27.819 ;
        RECT  24 2.137 24.12 27.819 ;
        RECT  21.3 2.137 21.42 27.819 ;
        RECT  18.6 2.137 18.72 27.819 ;
        RECT  15.9 2.137 16.02 27.819 ;
        RECT  13.2 2.137 13.32 27.819 ;
        RECT  10.5 2.137 10.62 27.819 ;
        RECT  7.8 2.137 7.92 27.819 ;
        RECT  5.1 2.137 5.22 27.819 ;
        RECT  2.4 2.137 2.52 27.819 ;
    END
  END VSS
  # OT_OBS_CLOSED layer=M5 d_um=1.536 added=20
  OBS
    LAYER RVTN ;
     RECT  2.16 2.16 62.586 2.295 ;
     RECT  2.16 2.565 62.586 2.835 ;
     RECT  2.16 3.105 62.586 3.375 ;
     RECT  2.16 3.645 62.586 3.915 ;
     RECT  2.16 4.185 62.586 4.455 ;
     RECT  2.16 4.725 62.586 4.995 ;
     RECT  2.16 5.265 62.586 5.535 ;
     RECT  2.16 5.805 62.586 6.075 ;
     RECT  2.16 6.345 62.586 6.615 ;
     RECT  2.16 6.885 62.586 7.155 ;
     RECT  2.16 7.425 62.586 7.695 ;
     RECT  2.16 7.965 62.586 8.235 ;
     RECT  2.16 8.505 62.586 8.775 ;
     RECT  2.16 9.045 62.586 9.315 ;
     RECT  2.16 9.585 62.586 9.855 ;
     RECT  2.16 10.125 62.586 10.395 ;
     RECT  2.16 10.665 62.586 10.935 ;
     RECT  2.16 11.205 62.586 11.475 ;
     RECT  2.16 11.745 62.586 12.015 ;
     RECT  2.16 12.285 62.586 12.555 ;
     RECT  2.16 12.825 62.586 13.095 ;
     RECT  2.16 13.365 62.586 13.635 ;
     RECT  2.16 13.905 62.586 14.175 ;
     RECT  2.16 14.445 62.586 14.715 ;
     RECT  2.16 14.985 62.586 15.255 ;
     RECT  2.16 15.525 62.586 15.795 ;
     RECT  2.16 16.065 62.586 16.335 ;
     RECT  2.16 16.605 62.586 16.875 ;
     RECT  2.16 17.145 62.586 17.415 ;
     RECT  2.16 17.685 62.586 17.955 ;
     RECT  2.16 18.225 62.586 18.495 ;
     RECT  2.16 18.765 62.586 19.035 ;
     RECT  2.16 19.305 62.586 19.575 ;
     RECT  2.16 19.845 62.586 20.115 ;
     RECT  2.16 20.385 62.586 20.655 ;
     RECT  2.16 20.925 62.586 21.195 ;
     RECT  2.16 21.465 62.586 21.735 ;
     RECT  2.16 22.005 62.586 22.275 ;
     RECT  2.16 22.545 62.586 22.815 ;
     RECT  2.16 23.085 62.586 23.355 ;
     RECT  2.16 23.625 62.586 23.895 ;
     RECT  2.16 24.165 62.586 24.435 ;
     RECT  2.16 24.705 62.586 24.975 ;
     RECT  2.16 25.245 62.586 25.515 ;
     RECT  2.16 25.785 62.586 26.055 ;
     RECT  2.16 26.325 62.586 26.595 ;
     RECT  2.16 26.865 62.586 27.135 ;
     RECT  2.16 27.405 62.586 27.675 ;
    LAYER RVTP ;
     RECT  2.16 2.295 62.586 2.565 ;
     RECT  2.16 2.835 62.586 3.105 ;
     RECT  2.16 3.375 62.586 3.645 ;
     RECT  2.16 3.915 62.586 4.185 ;
     RECT  2.16 4.455 62.586 4.725 ;
     RECT  2.16 4.995 62.586 5.265 ;
     RECT  2.16 5.535 62.586 5.805 ;
     RECT  2.16 6.075 62.586 6.345 ;
     RECT  2.16 6.615 62.586 6.885 ;
     RECT  2.16 7.155 62.586 7.425 ;
     RECT  2.16 7.695 62.586 7.965 ;
     RECT  2.16 8.235 62.586 8.505 ;
     RECT  2.16 8.775 62.586 9.045 ;
     RECT  2.16 9.315 62.586 9.585 ;
     RECT  2.16 9.855 62.586 10.125 ;
     RECT  2.16 10.395 62.586 10.665 ;
     RECT  2.16 10.935 62.586 11.205 ;
     RECT  2.16 11.475 62.586 11.745 ;
     RECT  2.16 12.015 62.586 12.285 ;
     RECT  2.16 12.555 62.586 12.825 ;
     RECT  2.16 13.095 62.586 13.365 ;
     RECT  2.16 13.635 62.586 13.905 ;
     RECT  2.16 14.175 62.586 14.445 ;
     RECT  2.16 14.715 62.586 14.985 ;
     RECT  2.16 15.255 62.586 15.525 ;
     RECT  2.16 15.795 62.586 16.065 ;
     RECT  2.16 16.335 62.586 16.605 ;
     RECT  2.16 16.875 62.586 17.145 ;
     RECT  2.16 17.415 62.586 17.685 ;
     RECT  2.16 17.955 62.586 18.225 ;
     RECT  2.16 18.495 62.586 18.765 ;
     RECT  2.16 19.035 62.586 19.305 ;
     RECT  2.16 19.575 62.586 19.845 ;
     RECT  2.16 20.115 62.586 20.385 ;
     RECT  2.16 20.655 62.586 20.925 ;
     RECT  2.16 21.195 62.586 21.465 ;
     RECT  2.16 21.735 62.586 22.005 ;
     RECT  2.16 22.275 62.586 22.545 ;
     RECT  2.16 22.815 62.586 23.085 ;
     RECT  2.16 23.355 62.586 23.625 ;
     RECT  2.16 23.895 62.586 24.165 ;
     RECT  2.16 24.435 62.586 24.705 ;
     RECT  2.16 24.975 62.586 25.245 ;
     RECT  2.16 25.515 62.586 25.785 ;
     RECT  2.16 26.055 62.586 26.325 ;
     RECT  2.16 26.595 62.586 26.865 ;
     RECT  2.16 27.135 62.586 27.405 ;
     RECT  2.16 27.675 62.586 27.81 ;
    LAYER M1 ;
     RECT  2.16 2.151 62.586 27.819 ;
    LAYER M2 ;
     RECT  0.031 12.906 0.103 12.924 ;
     RECT  0.031 18.936 0.103 18.954 ;
     RECT  0.103 18.621 0.139 18.954 ;
     RECT  0.103 12.186 0.203 13.194 ;
     RECT  0.103 21.132 0.203 21.15 ;
     RECT  0.103 22.446 0.203 22.959 ;
     RECT  0.103 15.156 0.427 15.75 ;
     RECT  0.203 12.258 0.463 13.194 ;
     RECT  0.427 15.156 0.463 16.434 ;
     RECT  0.103 17.424 0.463 17.442 ;
     RECT  0.139 18.576 0.463 18.954 ;
     RECT  0.103 20.196 0.463 20.214 ;
     RECT  0.427 11.106 0.499 11.124 ;
     RECT  0.463 17.424 0.499 18.954 ;
     RECT  0.463 19.818 0.499 20.214 ;
     RECT  0.499 11.016 0.535 11.124 ;
     RECT  0.463 12.258 0.535 16.434 ;
     RECT  0.499 17.424 0.535 20.214 ;
     RECT  0.463 21.168 0.535 21.564 ;
     RECT  0.535 11.016 2.16 11.232 ;
     RECT  0.535 12.258 2.16 20.214 ;
     RECT  0.535 21.168 2.16 21.996 ;
     RECT  0.203 22.896 2.16 22.914 ;
     RECT  31.639 30.114 31.811 30.132 ;
     RECT  2.16 2.151 62.586 27.819 ;
     RECT  62.586 6.624 62.807 19.53 ;
     RECT  62.807 9.396 62.915 19.098 ;
     RECT  62.807 6.624 63.311 8.226 ;
     RECT  62.915 9.396 63.311 18.864 ;
     RECT  63.311 6.624 63.347 7.992 ;
     RECT  63.311 9.828 63.347 12.654 ;
     RECT  63.347 7.974 63.383 7.992 ;
     RECT  63.311 13.716 63.383 16.128 ;
     RECT  63.347 9.828 63.887 9.846 ;
     RECT  63.347 10.746 63.887 12.51 ;
     RECT  63.383 13.716 63.887 15.714 ;
     RECT  63.311 17.46 63.887 18.864 ;
     RECT  63.347 6.624 63.923 7.218 ;
     RECT  63.887 13.986 63.923 15.246 ;
     RECT  63.887 18.27 63.923 18.324 ;
     RECT  63.923 6.858 63.995 6.876 ;
     RECT  63.923 18.306 63.995 18.324 ;
     RECT  63.887 11.52 64.615 11.538 ;
     RECT  64.615 11.52 64.643 12.276 ;
     RECT  64.651 9.486 64.751 9.504 ;
     RECT  64.643 12.186 64.751 12.276 ;
     RECT  64.651 18.774 64.751 18.792 ;
    LAYER M3 ;
     RECT  2.415 2.143 2.505 2.413 ;
     RECT  5.115 2.143 5.205 2.413 ;
     RECT  7.815 2.143 7.905 2.413 ;
     RECT  10.515 2.143 10.605 2.413 ;
     RECT  13.215 2.143 13.305 2.413 ;
     RECT  15.915 2.143 16.005 2.413 ;
     RECT  18.615 2.143 18.705 2.413 ;
     RECT  21.315 2.143 21.405 2.413 ;
     RECT  24.015 2.143 24.105 2.413 ;
     RECT  26.715 2.143 26.805 2.413 ;
     RECT  29.415 2.143 29.505 2.413 ;
     RECT  32.115 2.143 32.205 2.413 ;
     RECT  34.815 2.143 34.905 2.413 ;
     RECT  37.515 2.143 37.605 2.413 ;
     RECT  40.215 2.143 40.305 2.413 ;
     RECT  42.915 2.143 43.005 2.413 ;
     RECT  45.615 2.143 45.705 2.413 ;
     RECT  48.315 2.143 48.405 2.413 ;
     RECT  51.015 2.143 51.105 2.413 ;
     RECT  53.715 2.143 53.805 2.413 ;
     RECT  56.415 2.143 56.505 2.413 ;
     RECT  59.115 2.143 59.205 2.413 ;
     RECT  61.815 2.143 61.905 2.413 ;
     RECT  59.115 2.413 59.397 6.547 ;
     RECT  59.115 6.547 59.454 6.655 ;
     RECT  60.192 6.619 60.21 6.655 ;
     RECT  58.752 6.655 59.454 6.691 ;
     RECT  60.192 6.655 60.318 6.691 ;
     RECT  61.056 6.547 61.074 6.691 ;
     RECT  63.9 6.619 63.918 6.691 ;
     RECT  58.716 6.691 61.074 6.809 ;
     RECT  58.716 6.809 60.21 6.845 ;
     RECT  60.948 6.809 61.074 6.845 ;
     RECT  63.864 6.691 63.918 6.853 ;
     RECT  53.715 2.413 53.997 6.889 ;
     RECT  61.815 2.413 62.097 6.961 ;
     RECT  58.716 6.845 59.706 7.051 ;
     RECT  56.415 2.413 56.697 7.087 ;
     RECT  58.356 7.051 59.706 7.087 ;
     RECT  32.115 2.413 32.397 7.123 ;
     RECT  46.764 6.925 46.782 7.187 ;
     RECT  34.815 2.413 35.097 7.231 ;
     RECT  2.415 2.413 2.697 7.321 ;
     RECT  55.656 7.231 55.674 7.321 ;
     RECT  56.415 7.087 59.706 7.321 ;
     RECT  34.815 7.231 35.19 7.349 ;
     RECT  63.864 6.853 63.99 7.373 ;
     RECT  30.924 7.321 30.942 7.429 ;
     RECT  30.888 7.429 30.942 7.43 ;
     RECT  55.656 7.321 59.706 7.435 ;
     RECT  61.815 6.961 62.73 7.435 ;
     RECT  29.415 2.413 29.697 7.465 ;
     RECT  30.888 7.43 30.906 7.465 ;
     RECT  51.015 2.413 51.297 7.501 ;
     RECT  60.984 6.845 61.074 7.501 ;
     RECT  61.815 7.435 62.766 7.501 ;
     RECT  5.115 2.413 5.397 7.591 ;
     RECT  53.028 6.889 53.997 7.619 ;
     RECT  55.584 7.435 59.706 7.627 ;
     RECT  60.984 7.501 62.766 7.627 ;
     RECT  32.115 7.123 32.49 7.663 ;
     RECT  55.584 7.627 62.838 7.663 ;
     RECT  55.44 7.663 63.378 7.799 ;
     RECT  2.415 7.321 3.402 7.861 ;
     RECT  55.44 7.799 57.69 7.889 ;
     RECT  50.544 7.501 51.297 7.925 ;
     RECT  55.44 7.889 55.674 7.997 ;
     RECT  41.544 7.969 41.562 8.041 ;
     RECT  41.4 8.041 41.562 8.159 ;
     RECT  38.772 7.969 38.79 8.167 ;
     RECT  38.772 8.167 38.826 8.168 ;
     RECT  38.808 8.168 38.826 8.203 ;
     RECT  40.215 2.413 40.497 8.203 ;
     RECT  41.4 8.159 41.49 8.203 ;
     RECT  38.808 8.203 38.898 8.267 ;
     RECT  40.215 8.203 41.49 8.267 ;
     RECT  42.915 2.413 43.197 8.275 ;
     RECT  40.215 8.267 40.986 8.311 ;
     RECT  39.816 8.311 40.986 8.429 ;
     RECT  38.844 8.267 38.898 8.437 ;
     RECT  42.768 8.275 43.197 8.437 ;
     RECT  15.915 2.413 16.197 8.473 ;
     RECT  58.536 7.799 63.378 8.525 ;
     RECT  38.844 8.437 38.934 8.537 ;
     RECT  42.732 8.437 43.197 8.537 ;
     RECT  53.1 7.619 53.997 8.545 ;
     RECT  56.415 7.889 57.69 8.545 ;
     RECT  56.415 8.545 57.762 8.671 ;
     RECT  53.064 8.545 53.997 8.735 ;
     RECT  56.304 8.671 57.762 8.779 ;
     RECT  51.015 7.925 51.297 8.815 ;
     RECT  58.536 8.525 62.802 8.879 ;
     RECT  56.304 8.779 57.798 8.923 ;
     RECT  53.568 8.735 53.997 8.941 ;
     RECT  55.98 8.923 57.798 9.005 ;
     RECT  53.568 8.941 54.126 9.011 ;
     RECT  29.415 7.465 30.906 9.049 ;
     RECT  31.716 7.663 32.49 9.049 ;
     RECT  58.536 8.879 60.822 9.113 ;
     RECT  56.415 9.005 57.798 9.121 ;
     RECT  58.536 9.113 59.397 9.121 ;
     RECT  56.415 9.121 59.397 9.149 ;
     RECT  6.912 8.671 6.93 9.211 ;
     RECT  13.215 2.413 13.497 9.211 ;
     RECT  14.508 8.437 14.526 9.211 ;
     RECT  21.315 2.413 21.597 9.211 ;
     RECT  26.715 2.413 26.997 9.211 ;
     RECT  29.415 9.049 32.49 9.211 ;
     RECT  54.972 8.581 54.99 9.211 ;
     RECT  13.104 9.211 13.497 9.248 ;
     RECT  21.204 9.211 21.597 9.248 ;
     RECT  61.56 8.879 62.802 9.259 ;
     RECT  50.724 8.815 51.297 9.275 ;
     RECT  53.715 9.011 54.126 9.283 ;
     RECT  54.972 9.211 55.35 9.283 ;
     RECT  6.84 9.211 6.93 9.341 ;
     RECT  14.508 9.211 14.85 9.341 ;
     RECT  26.676 9.211 26.997 9.341 ;
     RECT  38.772 9.211 38.79 9.341 ;
     RECT  46.764 9.211 46.782 9.341 ;
     RECT  52.308 9.307 52.326 9.355 ;
     RECT  64.656 9.451 64.674 9.481 ;
     RECT  52.308 9.355 52.434 9.509 ;
     RECT  64.656 9.481 64.746 9.509 ;
     RECT  64.728 9.509 64.746 9.533 ;
     RECT  57.636 9.149 59.397 9.617 ;
     RECT  61.56 9.259 63.306 9.643 ;
     RECT  60.336 9.113 60.822 9.661 ;
     RECT  61.56 9.643 63.882 9.661 ;
     RECT  52.308 9.509 52.326 9.677 ;
     RECT  53.715 9.283 55.35 9.779 ;
     RECT  60.336 9.661 63.882 9.851 ;
     RECT  58.464 9.617 59.397 9.931 ;
     RECT  2.415 7.861 3.87 10.057 ;
     RECT  51.015 9.275 51.297 10.057 ;
     RECT  56.415 9.149 56.862 10.057 ;
     RECT  58.464 9.931 59.526 10.057 ;
     RECT  60.336 9.851 63.342 10.057 ;
     RECT  29.268 9.211 32.49 10.129 ;
     RECT  27.72 7.087 27.738 10.201 ;
     RECT  54.72 9.779 55.35 10.201 ;
     RECT  50.76 10.057 51.297 10.229 ;
     RECT  29.268 10.129 33.066 10.291 ;
     RECT  54.72 10.201 55.638 10.327 ;
     RECT  56.415 10.057 57.618 10.327 ;
     RECT  29.268 10.291 33.102 10.427 ;
     RECT  26.715 9.341 26.997 10.471 ;
     RECT  27.72 10.201 28.458 10.471 ;
     RECT  29.268 10.427 33.066 10.471 ;
     RECT  56.412 10.327 57.618 10.471 ;
     RECT  58.464 10.057 63.342 10.471 ;
     RECT  54.72 10.327 55.674 10.555 ;
     RECT  56.412 10.471 63.342 10.555 ;
     RECT  54.72 10.555 63.342 10.603 ;
     RECT  54.72 10.603 63.882 10.625 ;
     RECT  6.912 9.341 6.93 10.741 ;
     RECT  54.72 10.625 55.206 10.769 ;
     RECT  24.015 2.413 24.297 10.831 ;
     RECT  34.815 7.349 35.154 10.831 ;
     RECT  18.615 2.413 18.897 10.987 ;
     RECT  23.328 10.831 24.297 10.987 ;
     RECT  22.824 10.987 24.297 11.039 ;
     RECT  0.468 10.939 0.558 11.101 ;
     RECT  34.815 10.831 35.226 11.101 ;
     RECT  54.9 10.769 55.206 11.129 ;
     RECT  10.515 2.413 10.797 11.137 ;
     RECT  34.812 11.101 35.226 11.201 ;
     RECT  23.256 11.039 24.297 11.213 ;
     RECT  14.508 9.341 14.526 11.227 ;
     RECT  18.615 10.987 18.954 11.227 ;
     RECT  23.256 11.213 23.274 11.261 ;
     RECT  2.415 10.057 4.122 11.272 ;
     RECT  5.115 7.591 5.562 11.272 ;
     RECT  10.515 11.137 10.854 11.272 ;
     RECT  13.215 9.248 13.497 11.272 ;
     RECT  15.84 8.473 16.197 11.272 ;
     RECT  26.715 10.471 33.066 11.273 ;
     RECT  2.304 11.272 4.122 11.281 ;
     RECT  5.004 11.272 5.562 11.281 ;
     RECT  14.508 11.227 14.85 11.281 ;
     RECT  34.815 11.201 35.226 11.281 ;
     RECT  10.404 11.272 10.854 11.309 ;
     RECT  15.804 11.272 16.197 11.309 ;
     RECT  2.304 11.281 5.562 11.399 ;
     RECT  10.515 11.309 10.818 11.399 ;
     RECT  14.508 11.281 14.886 11.399 ;
     RECT  6.84 10.741 6.93 11.405 ;
     RECT  14.508 11.399 14.85 11.405 ;
     RECT  18.615 11.227 19.026 11.405 ;
     RECT  27.72 11.273 33.066 11.407 ;
     RECT  33.804 11.371 33.822 11.407 ;
     RECT  5.004 11.399 5.562 11.408 ;
     RECT  13.104 11.272 13.497 11.408 ;
     RECT  55.944 10.625 63.882 11.419 ;
     RECT  55.872 11.419 63.882 11.435 ;
     RECT  34.815 11.281 35.442 11.479 ;
     RECT  2.304 11.399 4.122 11.501 ;
     RECT  54.9 11.129 54.918 11.515 ;
     RECT  54.828 11.515 54.918 11.551 ;
     RECT  54.792 11.551 54.918 11.579 ;
     RECT  54.792 11.579 54.882 11.641 ;
     RECT  57.456 11.435 63.882 11.669 ;
     RECT  27.72 11.407 33.822 11.677 ;
     RECT  54.72 11.641 54.882 11.777 ;
     RECT  0.432 11.101 0.558 11.995 ;
     RECT  54.792 11.777 54.882 12.083 ;
     RECT  27.72 11.677 33.894 12.091 ;
     RECT  64.62 11.515 64.638 12.139 ;
     RECT  0.144 11.995 0.558 12.172 ;
     RECT  64.62 12.139 64.674 12.181 ;
     RECT  57.492 11.669 63.882 12.209 ;
     RECT  27.72 12.091 34.002 12.245 ;
     RECT  64.62 12.181 64.746 12.281 ;
     RECT  34.815 11.479 35.514 12.361 ;
     RECT  34.815 12.361 35.91 12.451 ;
     RECT  34.815 12.451 35.982 12.479 ;
     RECT  60.192 12.209 63.882 12.515 ;
     RECT  54.828 12.083 54.882 12.523 ;
     RECT  55.872 11.435 56.697 12.523 ;
     RECT  60.192 12.515 63.378 12.557 ;
     RECT  14.508 11.405 14.526 12.619 ;
     RECT  21.315 9.248 21.597 12.619 ;
     RECT  60.192 12.557 63.342 12.659 ;
     RECT  54.828 12.523 56.697 12.763 ;
     RECT  57.492 12.209 59.454 12.763 ;
     RECT  21.315 12.619 21.69 12.797 ;
     RECT  6.912 11.405 6.93 12.811 ;
     RECT  14.508 12.619 14.85 12.811 ;
     RECT  26.715 11.273 26.997 12.811 ;
     RECT  27.72 12.245 33.93 12.821 ;
     RECT  54.828 12.763 59.454 12.829 ;
     RECT  0.108 12.172 0.558 12.859 ;
     RECT  0.108 12.859 0.666 12.899 ;
     RECT  0.108 12.899 0.594 12.901 ;
     RECT  38.736 12.829 38.754 12.901 ;
     RECT  0.036 12.901 0.594 12.941 ;
     RECT  2.415 11.501 4.122 12.991 ;
     RECT  5.115 11.408 5.562 12.991 ;
     RECT  13.215 11.408 13.497 12.991 ;
     RECT  21.315 12.797 21.597 12.991 ;
     RECT  54.72 12.829 59.454 12.991 ;
     RECT  60.192 12.659 63.306 12.991 ;
     RECT  14.508 12.811 14.922 13.037 ;
     RECT  38.664 12.901 38.754 13.091 ;
     RECT  34.815 12.479 35.226 13.099 ;
     RECT  45.615 2.413 45.897 13.099 ;
     RECT  47.016 9.589 47.034 13.099 ;
     RECT  26.676 12.811 26.997 13.261 ;
     RECT  45.615 13.099 47.034 13.289 ;
     RECT  34.776 13.099 35.226 13.369 ;
     RECT  35.964 12.479 35.982 13.369 ;
     RECT  45.615 13.289 46.098 13.373 ;
     RECT  27.72 12.821 33.786 13.433 ;
     RECT  54.72 12.991 63.306 13.483 ;
     RECT  54.72 13.483 63.882 13.579 ;
     RECT  34.776 13.369 35.982 13.613 ;
     RECT  54.72 13.579 63.918 13.703 ;
     RECT  27.72 13.433 33.678 13.709 ;
     RECT  34.776 13.613 35.19 13.837 ;
     RECT  34.416 13.837 35.19 13.865 ;
     RECT  22.824 12.619 22.842 13.997 ;
     RECT  2.304 12.991 4.122 14.009 ;
     RECT  5.004 12.991 5.562 14.009 ;
     RECT  13.104 12.991 13.497 14.009 ;
     RECT  21.204 12.991 21.597 14.009 ;
     RECT  6.84 12.811 6.93 14.099 ;
     RECT  29.268 13.709 33.678 14.099 ;
     RECT  34.416 13.865 35.154 14.135 ;
     RECT  53.715 9.779 53.997 14.143 ;
     RECT  26.208 13.261 26.997 14.203 ;
     RECT  55.836 13.703 63.918 14.243 ;
     RECT  54.72 13.703 54.954 14.252 ;
     RECT  53.604 14.143 53.997 14.279 ;
     RECT  54.72 14.252 54.918 14.333 ;
     RECT  21.315 14.009 21.597 14.347 ;
     RECT  22.896 14.347 22.914 14.413 ;
     RECT  24.015 11.213 24.297 14.413 ;
     RECT  14.508 13.037 14.85 14.443 ;
     RECT  55.836 14.243 61.002 14.449 ;
     RECT  22.896 14.413 24.297 14.477 ;
     RECT  21.315 14.347 21.69 14.525 ;
     RECT  36.144 13.801 36.162 14.675 ;
     RECT  55.656 14.449 61.002 14.675 ;
     RECT  27.72 13.709 28.53 14.683 ;
     RECT  29.268 14.099 33.606 14.683 ;
     RECT  34.74 14.135 35.154 14.683 ;
     RECT  54.72 14.333 54.846 14.711 ;
     RECT  14.508 14.443 14.922 14.717 ;
     RECT  27.72 14.683 33.606 14.765 ;
     RECT  34.74 14.683 35.838 14.819 ;
     RECT  57.528 14.675 61.002 14.819 ;
     RECT  6.84 14.099 6.858 14.881 ;
     RECT  25.776 14.203 26.997 14.909 ;
     RECT  27.72 14.765 33.066 14.981 ;
     RECT  26.1 14.909 26.997 15.005 ;
     RECT  55.656 14.675 56.697 15.016 ;
     RECT  26.172 15.005 26.997 15.053 ;
     RECT  33.84 14.881 33.858 15.061 ;
     RECT  34.74 14.819 35.154 15.061 ;
     RECT  57.816 14.819 61.002 15.179 ;
     RECT  61.815 14.243 63.918 15.223 ;
     RECT  61.308 15.223 63.918 15.251 ;
     RECT  54.72 14.711 54.81 15.493 ;
     RECT  55.584 15.016 56.697 15.493 ;
     RECT  51.015 10.229 51.297 15.529 ;
     RECT  26.208 15.053 26.997 15.533 ;
     RECT  2.415 14.009 4.122 15.592 ;
     RECT  5.115 14.009 5.562 15.592 ;
     RECT  13.215 14.009 13.497 15.592 ;
     RECT  21.315 14.525 21.597 15.592 ;
     RECT  14.508 14.717 14.526 15.595 ;
     RECT  23.328 14.477 24.297 15.595 ;
     RECT  29.196 14.981 33.066 15.601 ;
     RECT  33.84 15.061 35.154 15.601 ;
     RECT  54.72 15.493 56.898 15.685 ;
     RECT  57.816 15.179 60.57 15.685 ;
     RECT  54.72 15.685 60.57 15.719 ;
     RECT  61.308 15.251 63.882 15.725 ;
     RECT  26.676 15.533 26.997 15.773 ;
     RECT  58.716 15.719 60.57 15.773 ;
     RECT  22.824 15.595 24.297 15.821 ;
     RECT  38.808 15.997 38.826 16.097 ;
     RECT  58.788 15.773 60.57 16.105 ;
     RECT  61.308 15.725 63.378 16.105 ;
     RECT  58.788 16.105 63.378 16.133 ;
     RECT  6.84 14.881 6.93 16.157 ;
     RECT  5.004 15.592 5.562 16.169 ;
     RECT  13.104 15.592 13.497 16.169 ;
     RECT  21.204 15.592 21.597 16.169 ;
     RECT  2.304 15.592 4.122 16.205 ;
     RECT  21.315 16.169 21.597 16.315 ;
     RECT  53.715 14.279 53.997 16.411 ;
     RECT  50.796 15.529 51.297 16.439 ;
     RECT  54.72 15.719 57.582 16.573 ;
     RECT  58.788 16.133 63.306 16.573 ;
     RECT  27.72 14.981 28.458 16.645 ;
     RECT  29.196 15.601 35.154 16.645 ;
     RECT  54.72 16.573 57.654 16.645 ;
     RECT  58.68 16.573 63.306 16.645 ;
     RECT  27.72 16.645 35.154 16.799 ;
     RECT  53.604 16.411 53.997 16.943 ;
     RECT  21.315 16.315 21.69 16.973 ;
     RECT  10.515 11.399 10.797 17.041 ;
     RECT  27.936 16.799 35.154 17.069 ;
     RECT  54.72 16.645 63.306 17.069 ;
     RECT  11.952 7.051 11.97 17.105 ;
     RECT  58.608 17.069 63.306 17.128 ;
     RECT  6.912 16.157 6.93 17.179 ;
     RECT  10.515 17.041 10.854 17.213 ;
     RECT  2.415 16.205 4.122 17.311 ;
     RECT  5.115 16.169 5.562 17.311 ;
     RECT  5.004 17.311 5.562 17.375 ;
     RECT  34.308 17.069 35.154 17.419 ;
     RECT  25.704 16.951 25.722 17.447 ;
     RECT  58.716 17.128 63.306 17.455 ;
     RECT  53.715 16.943 53.997 17.581 ;
     RECT  54.72 17.069 57.834 17.581 ;
     RECT  53.715 17.581 57.834 17.609 ;
     RECT  26.715 15.773 26.997 17.659 ;
     RECT  13.215 16.169 13.497 17.752 ;
     RECT  21.315 16.973 21.597 17.752 ;
     RECT  2.304 17.311 4.122 17.915 ;
     RECT  14.508 15.595 14.85 17.915 ;
     RECT  34.308 17.419 35.226 17.995 ;
     RECT  58.716 17.455 63.882 17.995 ;
     RECT  58.608 17.995 63.882 18.029 ;
     RECT  10.515 17.213 10.797 18.031 ;
     RECT  14.832 17.915 14.85 18.031 ;
     RECT  15.84 11.309 16.197 18.031 ;
     RECT  34.092 17.995 35.226 18.031 ;
     RECT  0.036 12.941 0.558 18.091 ;
     RECT  0.036 18.091 0.594 18.121 ;
     RECT  28.152 17.069 33.138 18.121 ;
     RECT  34.092 18.031 35.262 18.121 ;
     RECT  56.268 17.609 57.834 18.121 ;
     RECT  58.608 18.029 60.354 18.121 ;
     RECT  0.036 18.121 0.666 18.173 ;
     RECT  14.832 18.031 16.197 18.173 ;
     RECT  56.268 18.121 60.354 18.185 ;
     RECT  0.036 18.173 0.558 18.221 ;
     RECT  2.304 17.915 2.862 18.221 ;
     RECT  28.152 18.121 35.334 18.221 ;
     RECT  61.128 18.029 63.882 18.265 ;
     RECT  61.128 18.265 63.918 18.301 ;
     RECT  2.304 18.221 2.697 18.329 ;
     RECT  5.004 17.375 5.397 18.329 ;
     RECT  13.104 17.752 13.497 18.329 ;
     RECT  21.204 17.752 21.597 18.329 ;
     RECT  53.715 17.609 55.494 18.391 ;
     RECT  56.268 18.185 60.21 18.391 ;
     RECT  0.036 18.221 0.522 18.413 ;
     RECT  14.832 18.173 14.85 18.461 ;
     RECT  22.824 15.821 22.842 18.461 ;
     RECT  26.676 17.659 26.997 18.461 ;
     RECT  53.715 18.391 60.21 18.461 ;
     RECT  53.715 18.461 59.67 18.491 ;
     RECT  10.515 18.031 10.854 18.509 ;
     RECT  61.128 18.301 63.99 18.509 ;
     RECT  61.128 18.509 63.882 18.605 ;
     RECT  6.84 17.179 6.93 18.661 ;
     RECT  55.404 18.491 59.67 18.689 ;
     RECT  6.84 18.661 6.966 18.725 ;
     RECT  57.492 18.689 59.67 18.725 ;
     RECT  55.656 18.689 56.754 18.749 ;
     RECT  61.128 18.605 62.91 18.763 ;
     RECT  64.728 12.281 64.746 18.769 ;
     RECT  6.948 18.725 6.966 18.797 ;
     RECT  64.656 18.769 64.746 18.797 ;
     RECT  47.016 13.289 47.034 18.833 ;
     RECT  53.715 18.491 54.162 18.869 ;
     RECT  57.492 18.725 59.634 18.869 ;
     RECT  63.864 18.605 63.882 18.869 ;
     RECT  24.015 15.821 24.297 18.931 ;
     RECT  0.036 18.413 0.486 18.959 ;
     RECT  55.836 18.749 56.754 18.995 ;
     RECT  61.02 18.763 62.91 19.103 ;
     RECT  64.656 18.797 64.674 19.181 ;
     RECT  61.02 19.103 62.802 19.265 ;
     RECT  0.108 18.959 0.486 19.273 ;
     RECT  23.328 18.931 24.297 19.277 ;
     RECT  57.492 18.869 59.526 19.337 ;
     RECT  61.632 19.265 62.802 19.337 ;
     RECT  3.6 17.915 4.122 19.381 ;
     RECT  2.415 18.329 2.697 19.435 ;
     RECT  5.115 18.329 5.397 19.471 ;
     RECT  13.215 18.329 13.497 19.471 ;
     RECT  21.315 18.329 21.597 19.471 ;
     RECT  5.004 19.471 5.397 19.517 ;
     RECT  13.104 19.471 13.497 19.517 ;
     RECT  21.204 19.471 21.597 19.517 ;
     RECT  56.16 18.995 56.754 19.535 ;
     RECT  61.815 19.337 62.802 19.535 ;
     RECT  3.6 19.381 4.158 19.565 ;
     RECT  6.84 19.483 6.858 19.613 ;
     RECT  14.832 19.483 14.85 19.613 ;
     RECT  22.824 19.483 22.842 19.613 ;
     RECT  58.716 19.337 59.526 19.643 ;
     RECT  56.268 19.535 56.754 19.651 ;
     RECT  0.108 19.273 0.522 19.849 ;
     RECT  4.14 19.565 4.158 19.949 ;
     RECT  0.108 19.849 0.558 20.237 ;
     RECT  0.144 20.237 0.558 20.333 ;
     RECT  28.152 18.221 35.097 20.345 ;
     RECT  5.115 19.517 5.397 20.443 ;
     RECT  13.215 19.517 13.497 20.443 ;
     RECT  21.315 19.517 21.597 20.443 ;
     RECT  26.715 18.461 26.997 20.461 ;
     RECT  6.84 20.347 6.858 20.477 ;
     RECT  14.832 20.347 14.85 20.477 ;
     RECT  22.824 20.347 22.842 20.477 ;
     RECT  5.004 20.443 5.397 20.489 ;
     RECT  13.104 20.443 13.497 20.489 ;
     RECT  21.204 20.443 21.597 20.489 ;
     RECT  2.304 19.435 2.697 20.525 ;
     RECT  24.015 19.277 24.297 20.551 ;
     RECT  28.692 20.345 35.097 20.615 ;
     RECT  26.208 20.461 26.997 20.621 ;
     RECT  18.615 11.405 18.897 20.635 ;
     RECT  18.615 20.635 18.954 20.659 ;
     RECT  28.8 20.615 35.097 20.759 ;
     RECT  2.415 20.525 2.697 20.821 ;
     RECT  5.115 20.489 5.397 20.821 ;
     RECT  2.415 20.821 2.79 20.861 ;
     RECT  18.615 20.659 19.062 20.957 ;
     RECT  30.492 20.759 35.097 20.957 ;
     RECT  0.144 20.333 0.162 21.127 ;
     RECT  28.8 20.759 29.697 21.155 ;
     RECT  33.336 20.957 35.097 21.155 ;
     RECT  0.108 21.127 0.198 21.163 ;
     RECT  21.315 20.489 21.597 21.163 ;
     RECT  28.872 21.155 29.697 21.197 ;
     RECT  21.315 21.163 21.798 21.227 ;
     RECT  15.915 18.173 16.197 21.259 ;
     RECT  14.94 20.827 14.958 21.293 ;
     RECT  18.615 20.957 18.99 21.293 ;
     RECT  21.315 21.227 21.69 21.293 ;
     RECT  5.115 20.821 5.49 21.299 ;
     RECT  15.915 21.259 16.29 21.299 ;
     RECT  0.108 21.163 0.558 21.389 ;
     RECT  56.268 19.651 57.366 21.389 ;
     RECT  0.18 21.389 0.558 21.437 ;
     RECT  34.74 21.155 35.097 21.461 ;
     RECT  0.468 21.437 0.558 21.469 ;
     RECT  22.896 20.551 24.297 21.485 ;
     RECT  29.415 21.197 29.697 21.541 ;
     RECT  30.492 20.957 32.397 21.541 ;
     RECT  2.415 20.861 2.697 21.631 ;
     RECT  5.115 21.299 5.397 21.631 ;
     RECT  13.215 20.489 13.497 21.631 ;
     RECT  21.315 21.293 21.597 21.631 ;
     RECT  29.415 21.541 32.397 21.773 ;
     RECT  0.468 21.469 0.594 21.787 ;
     RECT  30.672 21.773 32.397 21.821 ;
     RECT  0.468 21.787 0.63 21.839 ;
     RECT  26.715 20.621 26.997 21.901 ;
     RECT  33.336 21.155 34.002 21.901 ;
     RECT  26.208 21.901 26.997 22.013 ;
     RECT  29.415 21.773 29.697 22.171 ;
     RECT  52.704 18.499 52.722 22.199 ;
     RECT  0.468 21.839 0.558 22.253 ;
     RECT  59.115 19.643 59.526 22.379 ;
     RECT  0.144 22.267 0.198 22.441 ;
     RECT  33.336 21.901 34.074 22.505 ;
     RECT  33.48 22.505 34.074 22.541 ;
     RECT  29.088 22.171 29.697 22.549 ;
     RECT  30.708 21.821 32.397 22.621 ;
     RECT  34.815 21.461 35.097 22.621 ;
     RECT  6.84 21.643 6.858 22.637 ;
     RECT  2.304 21.631 2.697 22.649 ;
     RECT  5.004 21.631 5.397 22.649 ;
     RECT  13.104 21.631 13.497 22.649 ;
     RECT  21.204 21.631 21.597 22.649 ;
     RECT  26.676 22.013 26.997 22.649 ;
     RECT  30.636 22.621 32.397 22.739 ;
     RECT  30.636 22.739 30.798 22.775 ;
     RECT  34.2 22.621 35.097 22.781 ;
     RECT  31.86 22.739 32.397 22.811 ;
     RECT  31.932 22.811 32.397 22.819 ;
     RECT  5.115 22.649 5.397 22.981 ;
     RECT  14.832 21.643 14.85 22.987 ;
     RECT  21.315 22.649 21.597 22.987 ;
     RECT  22.824 21.643 22.842 22.987 ;
     RECT  31.932 22.819 32.634 23.009 ;
     RECT  56.415 21.389 57.366 23.009 ;
     RECT  5.115 22.981 5.49 23.021 ;
     RECT  21.315 22.987 21.69 23.035 ;
     RECT  28.98 22.549 29.697 23.035 ;
     RECT  31.932 23.009 32.397 23.045 ;
     RECT  28.512 23.035 29.697 23.081 ;
     RECT  14.832 22.987 15.066 23.117 ;
     RECT  32.004 23.045 32.397 23.153 ;
     RECT  0.108 22.441 0.198 23.165 ;
     RECT  28.944 23.081 29.697 23.165 ;
     RECT  28.98 23.165 29.697 23.189 ;
     RECT  30.744 22.775 30.798 23.189 ;
     RECT  34.668 22.781 35.097 23.189 ;
     RECT  0.108 23.165 0.126 23.213 ;
     RECT  14.832 23.117 14.85 23.309 ;
     RECT  21.315 23.035 21.906 23.309 ;
     RECT  22.824 22.987 22.914 23.309 ;
     RECT  29.052 23.189 29.697 23.309 ;
     RECT  22.824 23.309 22.842 23.405 ;
     RECT  2.415 22.649 2.697 27.557 ;
     RECT  5.115 23.021 5.397 27.557 ;
     RECT  7.815 2.413 8.097 27.557 ;
     RECT  10.515 18.509 10.797 27.557 ;
     RECT  13.215 22.649 13.497 27.557 ;
     RECT  15.915 21.299 16.197 27.557 ;
     RECT  18.615 21.293 18.897 27.557 ;
     RECT  21.315 23.309 21.597 27.557 ;
     RECT  24.015 21.485 24.297 27.557 ;
     RECT  26.715 22.649 26.997 27.557 ;
     RECT  29.415 23.309 29.697 27.557 ;
     RECT  32.115 23.153 32.397 27.557 ;
     RECT  34.815 23.189 35.097 27.557 ;
     RECT  37.515 2.413 37.797 27.557 ;
     RECT  40.215 8.429 40.497 27.557 ;
     RECT  42.915 8.537 43.197 27.557 ;
     RECT  45.615 13.373 45.897 27.557 ;
     RECT  48.315 2.413 48.597 27.557 ;
     RECT  51.015 16.439 51.297 27.557 ;
     RECT  53.715 18.869 53.997 27.557 ;
     RECT  56.415 23.009 56.697 27.557 ;
     RECT  59.115 22.379 59.397 27.557 ;
     RECT  61.815 19.535 62.097 27.557 ;
     RECT  30.924 27.571 31.122 27.629 ;
     RECT  31.104 27.629 31.122 27.671 ;
     RECT  31.536 27.751 31.554 27.821 ;
     RECT  2.607 27.557 2.697 27.827 ;
     RECT  5.307 27.557 5.397 27.827 ;
     RECT  8.007 27.557 8.097 27.827 ;
     RECT  10.707 27.557 10.797 27.827 ;
     RECT  13.407 27.557 13.497 27.827 ;
     RECT  16.107 27.557 16.197 27.827 ;
     RECT  18.807 27.557 18.897 27.827 ;
     RECT  21.507 27.557 21.597 27.827 ;
     RECT  24.207 27.557 24.297 27.827 ;
     RECT  26.907 27.557 26.997 27.827 ;
     RECT  29.607 27.557 29.697 27.827 ;
     RECT  32.307 27.557 32.397 27.827 ;
     RECT  35.007 27.557 35.097 27.827 ;
     RECT  37.707 27.557 37.797 27.827 ;
     RECT  40.407 27.557 40.497 27.827 ;
     RECT  43.107 27.557 43.197 27.827 ;
     RECT  45.807 27.557 45.897 27.827 ;
     RECT  48.507 27.557 48.597 27.827 ;
     RECT  51.207 27.557 51.297 27.827 ;
     RECT  53.907 27.557 53.997 27.827 ;
     RECT  56.607 27.557 56.697 27.827 ;
     RECT  59.307 27.557 59.397 27.827 ;
     RECT  62.007 27.557 62.097 27.827 ;
     RECT  31.572 29.659 31.59 30.091 ;
     RECT  31.572 30.091 31.806 30.137 ;
     RECT  31.572 30.137 31.662 30.179 ;
     RECT  31.59 30.179 31.644 30.204 ;
    LAYER M4 ;
     RECT  0.084 10.992 0.457 11.016 ;
     RECT  0.06 11.016 0.457 11.088 ;
     RECT  0.084 11.088 0.457 11.112 ;
     RECT  0.06 11.112 0.457 11.184 ;
     RECT  0.084 11.184 0.457 11.208 ;
     RECT  0.06 11.208 0.457 11.28 ;
     RECT  0.084 11.28 0.457 11.304 ;
     RECT  0.06 11.304 0.457 11.376 ;
     RECT  0.084 11.376 0.457 11.4 ;
     RECT  0.06 11.4 0.457 11.472 ;
     RECT  0.084 11.472 0.457 11.496 ;
     RECT  0.06 11.496 0.457 11.568 ;
     RECT  0.084 11.568 0.457 11.592 ;
     RECT  0.06 11.592 0.457 11.664 ;
     RECT  0.084 11.664 0.457 11.688 ;
     RECT  0.06 11.688 0.457 11.76 ;
     RECT  0.084 11.76 0.457 11.784 ;
     RECT  0.06 11.784 0.457 11.856 ;
     RECT  0.084 11.856 0.457 11.88 ;
     RECT  0.06 11.88 0.457 11.952 ;
     RECT  0.084 11.952 0.457 11.976 ;
     RECT  0.06 11.976 0.457 12.048 ;
     RECT  0.084 12.048 0.457 12.072 ;
     RECT  0.06 12.072 0.457 12.144 ;
     RECT  0.084 12.144 0.457 12.168 ;
     RECT  0.06 12.168 0.457 12.24 ;
     RECT  0.084 12.24 0.457 12.264 ;
     RECT  0.06 12.264 0.457 12.336 ;
     RECT  0.084 12.336 0.457 12.36 ;
     RECT  0.06 12.36 0.457 12.432 ;
     RECT  0.084 12.432 0.457 12.456 ;
     RECT  0.06 12.456 0.457 12.528 ;
     RECT  0.084 12.528 0.457 12.552 ;
     RECT  0.06 12.552 0.457 12.624 ;
     RECT  0.084 12.624 0.457 12.648 ;
     RECT  0.06 12.648 0.457 12.72 ;
     RECT  0.084 12.72 0.457 12.744 ;
     RECT  0.06 12.744 0.457 12.816 ;
     RECT  0.084 12.816 0.457 12.84 ;
     RECT  0.06 12.84 0.457 12.912 ;
     RECT  0.084 12.912 0.457 12.936 ;
     RECT  0.06 12.936 0.457 13.008 ;
     RECT  0.084 13.008 0.457 13.032 ;
     RECT  0.06 13.032 0.457 13.104 ;
     RECT  0.084 13.104 0.457 13.128 ;
     RECT  0.06 13.128 0.457 13.2 ;
     RECT  0.084 13.2 0.457 13.224 ;
     RECT  0.06 13.224 0.457 13.296 ;
     RECT  0.084 13.296 0.457 13.32 ;
     RECT  0.06 13.32 0.457 13.392 ;
     RECT  0.084 13.392 0.457 13.416 ;
     RECT  0.06 13.416 0.457 13.488 ;
     RECT  0.084 13.488 0.457 13.512 ;
     RECT  0.06 13.512 0.457 13.584 ;
     RECT  0.084 13.584 0.457 13.608 ;
     RECT  0.06 13.608 0.457 13.68 ;
     RECT  0.084 13.68 0.457 13.704 ;
     RECT  0.06 13.704 0.457 13.776 ;
     RECT  0.084 13.776 0.457 13.8 ;
     RECT  0.06 13.8 0.457 13.872 ;
     RECT  0.084 13.872 0.457 13.896 ;
     RECT  0.06 13.896 0.457 13.968 ;
     RECT  0.084 13.968 0.457 13.992 ;
     RECT  0.06 13.992 0.457 14.064 ;
     RECT  0.084 14.064 0.457 14.088 ;
     RECT  0.06 14.088 0.457 14.16 ;
     RECT  0.084 14.16 0.457 14.184 ;
     RECT  0.06 14.184 0.457 14.256 ;
     RECT  0.084 14.256 0.457 14.28 ;
     RECT  0.06 14.28 0.457 14.352 ;
     RECT  0.084 14.352 0.457 14.376 ;
     RECT  0.06 14.376 0.457 14.448 ;
     RECT  0.084 14.448 0.457 14.472 ;
     RECT  0.06 14.472 0.457 14.544 ;
     RECT  0.084 14.544 0.457 14.568 ;
     RECT  0.06 14.568 0.457 14.64 ;
     RECT  0.084 14.64 0.457 14.664 ;
     RECT  0.06 14.664 0.457 14.736 ;
     RECT  0.084 14.736 0.457 14.76 ;
     RECT  0.06 14.76 0.457 14.832 ;
     RECT  0.084 14.832 0.457 14.856 ;
     RECT  0.06 14.856 0.457 14.928 ;
     RECT  0.084 14.928 0.457 14.952 ;
     RECT  0.06 14.952 0.457 15.024 ;
     RECT  0.084 15.024 0.457 15.048 ;
     RECT  0.06 15.048 0.457 15.12 ;
     RECT  0.084 15.12 0.457 15.144 ;
     RECT  0.06 15.144 0.457 15.216 ;
     RECT  0.084 15.216 0.457 15.24 ;
     RECT  0.06 15.24 0.457 15.312 ;
     RECT  0.084 15.312 0.457 15.336 ;
     RECT  0.06 15.336 0.457 15.408 ;
     RECT  0.084 15.408 0.457 15.432 ;
     RECT  0.06 15.432 0.457 15.504 ;
     RECT  0.084 15.504 0.457 15.528 ;
     RECT  0.06 15.528 0.457 15.6 ;
     RECT  0.084 15.6 0.457 15.624 ;
     RECT  0.06 15.624 0.457 15.696 ;
     RECT  0.084 15.696 0.457 15.72 ;
     RECT  0.06 15.72 0.457 15.792 ;
     RECT  0.084 15.792 0.457 15.816 ;
     RECT  0.06 15.816 0.457 15.888 ;
     RECT  0.084 15.888 0.457 15.912 ;
     RECT  0.06 15.912 0.457 15.984 ;
     RECT  0.084 15.984 0.457 16.008 ;
     RECT  0.06 16.008 0.457 16.08 ;
     RECT  0.084 16.08 0.457 16.104 ;
     RECT  0.06 16.104 0.457 16.176 ;
     RECT  0.084 16.176 0.457 16.2 ;
     RECT  0.06 16.2 0.457 16.272 ;
     RECT  0.084 16.272 0.457 16.296 ;
     RECT  0.06 16.296 0.457 16.368 ;
     RECT  0.084 16.368 0.457 16.392 ;
     RECT  0.06 16.392 0.457 16.464 ;
     RECT  0.084 16.464 0.457 16.488 ;
     RECT  0.06 16.488 0.457 16.56 ;
     RECT  0.084 16.56 0.457 16.584 ;
     RECT  0.06 16.584 0.457 16.656 ;
     RECT  0.084 16.656 0.457 16.68 ;
     RECT  0.06 16.68 0.457 16.752 ;
     RECT  0.084 16.752 0.457 16.776 ;
     RECT  0.06 16.776 0.457 16.848 ;
     RECT  0.084 16.848 0.457 16.872 ;
     RECT  0.06 16.872 0.457 16.944 ;
     RECT  0.084 16.944 0.457 16.968 ;
     RECT  0.06 16.968 0.457 17.04 ;
     RECT  0.084 17.04 0.457 17.064 ;
     RECT  0.06 17.064 0.457 17.136 ;
     RECT  0.084 17.136 0.457 17.16 ;
     RECT  0.06 17.16 0.457 17.232 ;
     RECT  0.084 17.232 0.457 17.256 ;
     RECT  0.06 17.256 0.457 17.328 ;
     RECT  0.084 17.328 0.457 17.352 ;
     RECT  0.06 17.352 0.457 17.424 ;
     RECT  0.084 17.424 0.457 17.448 ;
     RECT  0.06 17.448 0.457 17.52 ;
     RECT  0.084 17.52 0.457 17.544 ;
     RECT  0.06 17.544 0.457 17.616 ;
     RECT  0.084 17.616 0.457 17.64 ;
     RECT  0.06 17.64 0.457 17.712 ;
     RECT  0.084 17.712 0.457 17.736 ;
     RECT  0.06 17.736 0.457 17.808 ;
     RECT  0.084 17.808 0.457 17.832 ;
     RECT  0.06 17.832 0.457 17.904 ;
     RECT  0.084 17.904 0.457 17.928 ;
     RECT  0.06 17.928 0.457 18 ;
     RECT  0.084 18 0.457 18.024 ;
     RECT  0.06 18.024 0.457 18.096 ;
     RECT  0.084 18.096 0.457 18.12 ;
     RECT  0.06 18.12 0.457 18.192 ;
     RECT  0.084 18.192 0.457 18.216 ;
     RECT  0.06 18.216 0.457 18.288 ;
     RECT  0.084 18.288 0.457 18.312 ;
     RECT  0.06 18.312 0.457 18.384 ;
     RECT  0.084 18.384 0.457 18.408 ;
     RECT  0.06 18.408 0.457 18.48 ;
     RECT  0.084 18.48 0.457 18.504 ;
     RECT  0.06 18.504 0.457 18.576 ;
     RECT  0.084 18.576 0.457 18.6 ;
     RECT  0.06 18.6 0.457 18.672 ;
     RECT  0.084 18.672 0.457 18.696 ;
     RECT  0.06 18.696 0.457 18.768 ;
     RECT  0.084 18.768 0.457 18.792 ;
     RECT  0.06 18.792 0.457 18.864 ;
     RECT  0.084 18.864 0.457 18.888 ;
     RECT  0.06 18.888 0.457 18.96 ;
     RECT  0.084 18.96 0.457 18.984 ;
     RECT  0.06 18.984 0.457 19.056 ;
     RECT  0.084 19.056 0.457 19.08 ;
     RECT  0.06 19.08 0.457 19.152 ;
     RECT  0.084 19.152 0.457 19.176 ;
     RECT  0.06 19.176 0.457 19.248 ;
     RECT  0.084 19.248 0.457 19.272 ;
     RECT  0.06 19.272 0.457 19.344 ;
     RECT  0.084 19.344 0.457 19.368 ;
     RECT  0.06 19.368 0.457 19.44 ;
     RECT  0.084 19.44 0.457 19.464 ;
     RECT  0.06 19.464 0.457 19.536 ;
     RECT  0.084 19.536 0.457 19.56 ;
     RECT  0.06 19.56 0.457 19.632 ;
     RECT  0.084 19.632 0.457 19.656 ;
     RECT  0.06 19.656 0.457 19.728 ;
     RECT  0.084 19.728 0.457 19.752 ;
     RECT  0.06 19.752 0.457 19.824 ;
     RECT  0.084 19.824 0.457 19.848 ;
     RECT  0.06 19.848 0.457 19.92 ;
     RECT  0.084 19.92 0.457 19.944 ;
     RECT  0.06 19.944 0.457 20.016 ;
     RECT  0.084 20.016 0.457 20.04 ;
     RECT  0.06 20.04 0.457 20.112 ;
     RECT  0.084 20.112 0.457 20.136 ;
     RECT  0.06 20.136 0.457 20.208 ;
     RECT  0.084 20.208 0.457 20.232 ;
     RECT  0.06 20.232 0.457 20.304 ;
     RECT  0.084 20.304 0.457 20.328 ;
     RECT  0.06 20.328 0.457 20.4 ;
     RECT  0.084 20.4 0.457 20.424 ;
     RECT  0.06 20.424 0.457 20.496 ;
     RECT  0.084 20.496 0.457 20.52 ;
     RECT  0.06 20.52 0.457 20.592 ;
     RECT  0.084 20.592 0.457 20.616 ;
     RECT  0.06 20.616 0.457 20.688 ;
     RECT  0.084 20.688 0.457 20.712 ;
     RECT  0.06 20.712 0.457 20.784 ;
     RECT  0.084 20.784 0.457 20.808 ;
     RECT  0.06 20.808 0.457 20.88 ;
     RECT  0.084 20.88 0.457 20.904 ;
     RECT  0.06 20.904 0.457 20.976 ;
     RECT  0.084 20.976 0.457 21 ;
     RECT  0.06 21 0.457 21.072 ;
     RECT  0.084 21.072 0.457 21.096 ;
     RECT  0.06 21.096 0.457 21.168 ;
     RECT  0.084 21.168 0.457 21.192 ;
     RECT  0.06 21.192 0.457 21.264 ;
     RECT  0.084 21.264 0.457 21.288 ;
     RECT  0.06 21.288 0.457 21.36 ;
     RECT  0.084 21.36 0.457 21.384 ;
     RECT  0.06 21.384 0.457 21.456 ;
     RECT  0.084 21.456 0.457 21.48 ;
     RECT  0.06 21.48 0.457 21.552 ;
     RECT  0.084 21.552 0.457 21.576 ;
     RECT  0.06 21.576 0.457 21.648 ;
     RECT  0.084 21.648 0.457 21.672 ;
     RECT  0.06 21.672 0.457 21.744 ;
     RECT  0.084 21.744 0.457 21.768 ;
     RECT  0.06 21.768 0.457 21.84 ;
     RECT  0.084 21.84 0.457 21.864 ;
     RECT  0.06 21.864 0.457 21.936 ;
     RECT  0.084 21.936 0.457 21.96 ;
     RECT  0.06 21.96 0.457 22.032 ;
     RECT  0.084 22.032 0.457 22.056 ;
     RECT  0.06 22.056 0.457 22.128 ;
     RECT  0.084 22.128 0.457 22.152 ;
     RECT  0.06 22.152 0.457 22.224 ;
     RECT  0.084 22.224 0.457 22.248 ;
     RECT  0.06 22.248 0.457 22.32 ;
     RECT  0.084 22.32 0.457 22.344 ;
     RECT  0.06 22.344 0.457 22.416 ;
     RECT  0.084 22.416 0.457 22.44 ;
     RECT  0.06 22.44 0.457 22.512 ;
     RECT  0.084 22.512 0.457 22.536 ;
     RECT  0.06 22.536 0.457 22.608 ;
     RECT  0.084 22.608 0.457 22.632 ;
     RECT  0.06 22.632 0.457 22.704 ;
     RECT  0.084 22.704 0.457 22.728 ;
     RECT  0.06 22.728 0.457 22.8 ;
     RECT  0.084 22.8 0.457 22.824 ;
     RECT  0.06 22.824 0.457 22.896 ;
     RECT  0.084 22.896 0.457 22.92 ;
     RECT  0.06 22.92 0.457 22.992 ;
     RECT  0.084 22.992 0.457 23.016 ;
     RECT  0.06 23.016 0.457 23.088 ;
     RECT  0.084 23.088 0.457 23.112 ;
     RECT  0.06 23.112 0.457 23.184 ;
     RECT  0.084 23.184 0.457 23.208 ;
     RECT  0.06 23.208 0.457 23.28 ;
     RECT  0.084 23.28 0.457 23.304 ;
     RECT  0.457 10.944 0.569 23.304 ;
     RECT  0.569 10.992 2.408 23.304 ;
     RECT  2.408 2.148 2.512 27.552 ;
     RECT  2.512 2.418 2.6 27.552 ;
     RECT  2.6 2.418 2.704 27.822 ;
     RECT  2.704 10.992 2.765 23.304 ;
     RECT  2.704 9.312 5.108 9.336 ;
     RECT  2.765 11.136 5.108 23.304 ;
     RECT  5.108 2.148 5.212 27.552 ;
     RECT  5.212 2.418 5.3 27.552 ;
     RECT  5.3 2.418 5.404 27.822 ;
     RECT  5.404 9.216 6.829 9.24 ;
     RECT  6.829 9.216 7.808 9.336 ;
     RECT  5.404 11.136 7.808 23.304 ;
     RECT  7.808 2.148 7.912 27.552 ;
     RECT  7.912 2.418 8 27.552 ;
     RECT  8 2.418 8.104 27.822 ;
     RECT  8.104 9.312 10.508 9.336 ;
     RECT  8.104 11.136 10.508 23.304 ;
     RECT  10.508 2.148 10.612 27.552 ;
     RECT  10.612 2.418 10.7 27.552 ;
     RECT  10.7 2.418 10.804 27.822 ;
     RECT  10.804 9.216 13.208 9.24 ;
     RECT  10.804 11.136 13.208 23.304 ;
     RECT  13.208 2.148 13.312 27.552 ;
     RECT  13.312 2.418 13.4 27.552 ;
     RECT  13.4 2.418 13.504 27.822 ;
     RECT  13.504 9.216 14.821 9.24 ;
     RECT  14.821 9.216 14.861 9.336 ;
     RECT  14.861 9.312 15.908 9.336 ;
     RECT  13.504 11.136 15.908 23.304 ;
     RECT  15.908 2.148 16.012 27.552 ;
     RECT  16.012 2.418 16.1 27.552 ;
     RECT  16.1 2.418 16.204 27.822 ;
     RECT  16.204 9.312 18.608 9.336 ;
     RECT  16.204 11.136 18.608 23.304 ;
     RECT  18.608 2.148 18.712 27.552 ;
     RECT  18.712 2.418 18.8 27.552 ;
     RECT  18.8 2.418 18.904 27.822 ;
     RECT  18.904 9.216 21.308 9.24 ;
     RECT  18.904 10.992 21.308 23.304 ;
     RECT  21.308 2.148 21.412 27.552 ;
     RECT  21.412 2.418 21.5 27.552 ;
     RECT  21.5 2.418 21.604 27.822 ;
     RECT  21.604 10.992 22.789 23.304 ;
     RECT  22.789 10.992 22.853 23.4 ;
     RECT  22.853 11.136 22.876 23.4 ;
     RECT  21.604 9.216 23.893 9.24 ;
     RECT  23.893 9.216 24.008 9.336 ;
     RECT  22.876 11.136 24.008 23.304 ;
     RECT  24.008 2.148 24.112 27.552 ;
     RECT  24.112 2.418 24.2 27.552 ;
     RECT  24.2 2.418 24.304 27.822 ;
     RECT  24.304 9.312 26.708 9.336 ;
     RECT  24.304 11.136 26.708 23.304 ;
     RECT  26.708 2.148 26.812 27.552 ;
     RECT  26.812 2.418 26.9 27.552 ;
     RECT  26.9 2.418 27.004 27.822 ;
     RECT  27.004 9.312 29.408 9.336 ;
     RECT  27.004 11.136 29.408 23.304 ;
     RECT  29.408 2.148 29.512 27.552 ;
     RECT  29.512 2.418 29.6 27.552 ;
     RECT  29.6 2.418 29.704 27.822 ;
     RECT  29.704 11.136 29.981 22.776 ;
     RECT  29.981 11.136 30.197 19.08 ;
     RECT  30.197 11.136 30.233 14.76 ;
     RECT  30.197 16.08 30.233 19.08 ;
     RECT  30.233 18.96 30.521 19.08 ;
     RECT  30.233 16.08 30.593 17.448 ;
     RECT  30.233 11.136 30.737 14.472 ;
     RECT  29.704 9.216 30.769 9.24 ;
     RECT  30.737 11.136 30.773 14.232 ;
     RECT  30.521 18.96 30.773 18.984 ;
     RECT  29.981 20.4 30.773 22.776 ;
     RECT  30.769 9.216 30.809 9.336 ;
     RECT  30.593 16.08 30.809 16.968 ;
     RECT  30.773 20.4 30.809 20.952 ;
     RECT  30.773 11.28 31.025 14.232 ;
     RECT  30.809 16.08 31.025 16.92 ;
     RECT  30.913 27.6 31.484 27.624 ;
     RECT  31.517 29.664 31.601 29.688 ;
     RECT  31.669 30.096 31.817 30.12 ;
     RECT  30.809 9.312 32.108 9.336 ;
     RECT  31.025 11.952 32.108 14.232 ;
     RECT  31.025 16.128 32.108 16.92 ;
     RECT  30.809 20.928 32.108 20.952 ;
     RECT  30.773 21.936 32.108 22.776 ;
     RECT  31.484 27.6 32.108 27.816 ;
     RECT  32.108 2.148 32.212 27.816 ;
     RECT  32.212 2.418 32.3 27.816 ;
     RECT  32.3 2.418 32.404 27.822 ;
     RECT  32.404 20.928 32.645 20.952 ;
     RECT  32.404 11.952 33.077 14.808 ;
     RECT  32.404 16.848 33.113 17.112 ;
     RECT  33.077 11.952 33.149 14.76 ;
     RECT  33.149 11.952 33.505 14.232 ;
     RECT  33.505 11.472 33.509 14.232 ;
     RECT  32.404 22.512 33.509 22.776 ;
     RECT  33.509 11.472 33.689 11.976 ;
     RECT  33.689 11.472 33.761 11.496 ;
     RECT  33.113 16.848 34.405 16.872 ;
     RECT  32.404 9.312 34.808 9.336 ;
     RECT  33.509 13.104 34.808 14.232 ;
     RECT  34.405 16.368 34.808 16.872 ;
     RECT  33.509 22.752 34.808 22.776 ;
     RECT  32.404 27.6 34.808 27.624 ;
     RECT  34.808 2.148 34.912 27.624 ;
     RECT  34.912 2.418 35 27.624 ;
     RECT  35 2.418 35.104 27.822 ;
     RECT  35.104 9.312 37.508 9.336 ;
     RECT  35.104 13.344 37.508 14.232 ;
     RECT  35.104 27.6 37.508 27.624 ;
     RECT  37.508 2.148 37.612 27.624 ;
     RECT  37.612 2.418 37.7 27.624 ;
     RECT  37.7 2.418 37.804 27.822 ;
     RECT  37.804 9.216 38.801 9.336 ;
     RECT  38.801 9.312 40.208 9.336 ;
     RECT  37.804 13.344 40.208 14.232 ;
     RECT  37.804 27.6 40.208 27.624 ;
     RECT  40.208 2.148 40.312 27.624 ;
     RECT  40.312 2.418 40.4 27.624 ;
     RECT  40.4 2.418 40.504 27.822 ;
     RECT  40.504 9.312 42.908 9.336 ;
     RECT  40.504 13.344 42.908 14.232 ;
     RECT  40.504 27.6 42.908 27.624 ;
     RECT  42.908 2.148 43.012 27.624 ;
     RECT  43.012 2.418 43.1 27.624 ;
     RECT  43.1 2.418 43.204 27.822 ;
     RECT  43.204 9.312 45.608 9.336 ;
     RECT  43.204 13.344 45.608 14.232 ;
     RECT  43.204 27.6 45.608 27.624 ;
     RECT  45.608 2.148 45.712 27.624 ;
     RECT  45.712 2.418 45.8 27.624 ;
     RECT  45.8 2.418 45.904 27.822 ;
     RECT  45.904 13.104 46.109 14.232 ;
     RECT  46.109 13.104 46.477 13.128 ;
     RECT  45.904 9.216 46.793 9.576 ;
     RECT  46.793 9.312 48.308 9.576 ;
     RECT  46.109 14.208 48.308 14.232 ;
     RECT  45.904 27.6 48.308 27.624 ;
     RECT  48.308 2.148 48.412 27.624 ;
     RECT  48.412 2.418 48.5 27.624 ;
     RECT  48.5 2.418 48.604 27.822 ;
     RECT  48.604 9.312 51.008 9.576 ;
     RECT  48.604 14.208 51.008 14.232 ;
     RECT  48.604 27.6 51.008 27.624 ;
     RECT  51.008 2.148 51.112 27.624 ;
     RECT  51.112 2.418 51.2 27.624 ;
     RECT  51.2 2.418 51.304 27.822 ;
     RECT  51.304 9.312 52.337 9.672 ;
     RECT  52.337 9.36 53.516 9.528 ;
     RECT  53.516 8.976 53.557 9.528 ;
     RECT  53.557 8.976 53.708 9.864 ;
     RECT  51.304 14.208 53.708 14.232 ;
     RECT  51.304 27.6 53.708 27.624 ;
     RECT  53.708 2.148 53.812 27.624 ;
     RECT  53.812 2.418 53.9 27.624 ;
     RECT  53.9 2.418 54.004 27.822 ;
     RECT  54.004 27.6 54.563 27.624 ;
     RECT  54.004 16.176 55.033 18.024 ;
     RECT  54.004 11.568 55.177 12.648 ;
     RECT  55.033 15.84 55.321 18.024 ;
     RECT  54.004 8.976 55.333 9.864 ;
     RECT  55.321 15.792 55.393 18.024 ;
     RECT  55.429 7.68 55.573 7.944 ;
     RECT  54.004 13.68 55.573 14.328 ;
     RECT  55.393 15.792 55.573 18.552 ;
     RECT  55.573 7.44 55.645 7.944 ;
     RECT  55.333 8.928 55.645 9.864 ;
     RECT  55.573 13.68 55.645 18.552 ;
     RECT  55.645 13.68 55.825 18.744 ;
     RECT  55.645 7.44 55.933 9.864 ;
     RECT  55.177 10.992 55.933 12.648 ;
     RECT  55.933 7.44 56.005 12.648 ;
     RECT  55.825 13.68 56.005 18.984 ;
     RECT  56.005 7.44 56.149 18.984 ;
     RECT  56.149 7.44 56.408 19.272 ;
     RECT  56.408 2.148 56.512 27.552 ;
     RECT  56.512 2.418 56.6 27.552 ;
     RECT  56.6 2.418 56.704 27.822 ;
     RECT  56.704 12.768 56.765 19.272 ;
     RECT  56.765 12.768 56.981 18.168 ;
     RECT  56.704 7.44 57.011 11.784 ;
     RECT  57.011 7.44 57.449 9.144 ;
     RECT  57.449 8.784 57.809 9.144 ;
     RECT  56.981 12.816 57.845 18.168 ;
     RECT  57.985 9.168 58.165 9.192 ;
     RECT  57.011 10.224 58.165 11.784 ;
     RECT  58.165 9.168 58.417 11.784 ;
     RECT  57.845 12.816 58.417 17.112 ;
     RECT  57.449 7.44 58.492 7.752 ;
     RECT  57.845 18.144 58.561 18.168 ;
     RECT  56.765 19.248 58.561 19.272 ;
     RECT  58.492 7.392 58.597 7.752 ;
     RECT  58.597 7.392 58.705 7.896 ;
     RECT  58.417 9.168 58.885 17.112 ;
     RECT  58.705 7.104 58.921 7.896 ;
     RECT  58.921 7.104 58.957 7.944 ;
     RECT  58.885 8.976 58.957 17.112 ;
     RECT  58.957 7.104 59.065 17.112 ;
     RECT  58.561 18.144 59.065 19.272 ;
     RECT  59.065 7.104 59.108 19.272 ;
     RECT  59.108 2.148 59.212 27.552 ;
     RECT  59.212 2.418 59.3 27.552 ;
     RECT  59.3 2.418 59.404 27.822 ;
     RECT  59.404 7.392 59.717 9 ;
     RECT  59.717 7.728 60.401 9 ;
     RECT  59.404 10.08 60.473 17.448 ;
     RECT  60.473 13.824 60.565 17.448 ;
     RECT  59.404 18.432 60.565 18.456 ;
     RECT  60.401 7.728 60.617 7.992 ;
     RECT  60.617 7.728 60.761 7.944 ;
     RECT  60.401 8.976 61.549 9 ;
     RECT  60.473 10.08 61.549 12.84 ;
     RECT  61.549 8.976 61.765 12.84 ;
     RECT  60.565 13.824 61.765 18.792 ;
     RECT  60.761 7.92 61.808 7.944 ;
     RECT  61.765 8.976 61.808 18.792 ;
     RECT  61.808 2.148 61.912 27.552 ;
     RECT  61.912 2.418 62 27.552 ;
     RECT  62 2.418 62.104 27.822 ;
     RECT  62.104 7.152 63.853 19.08 ;
     RECT  63.853 6.864 64.645 19.08 ;
     RECT  64.645 6.864 64.692 6.888 ;
     RECT  64.645 6.888 64.716 6.96 ;
     RECT  64.645 6.96 64.692 6.984 ;
     RECT  64.645 6.984 64.716 7.056 ;
     RECT  64.645 7.056 64.692 7.08 ;
     RECT  64.645 7.08 64.716 7.152 ;
     RECT  64.645 7.152 64.692 7.176 ;
     RECT  64.645 7.176 64.716 7.248 ;
     RECT  64.645 7.248 64.692 7.272 ;
     RECT  64.645 7.272 64.716 7.344 ;
     RECT  64.645 7.344 64.692 7.368 ;
     RECT  64.645 7.368 64.716 7.44 ;
     RECT  64.645 7.44 64.692 7.464 ;
     RECT  64.645 7.464 64.716 7.536 ;
     RECT  64.645 7.536 64.692 7.56 ;
     RECT  64.645 7.56 64.716 7.632 ;
     RECT  64.645 7.632 64.692 7.656 ;
     RECT  64.645 7.656 64.716 7.728 ;
     RECT  64.645 7.728 64.692 7.752 ;
     RECT  64.645 7.752 64.716 7.824 ;
     RECT  64.645 7.824 64.692 7.848 ;
     RECT  64.645 7.848 64.716 7.92 ;
     RECT  64.645 7.92 64.692 7.944 ;
     RECT  64.645 7.944 64.716 8.016 ;
     RECT  64.645 8.016 64.692 8.04 ;
     RECT  64.645 8.04 64.716 8.112 ;
     RECT  64.645 8.112 64.692 8.136 ;
     RECT  64.645 8.136 64.716 8.208 ;
     RECT  64.645 8.208 64.692 8.232 ;
     RECT  64.645 8.232 64.716 8.304 ;
     RECT  64.645 8.304 64.692 8.328 ;
     RECT  64.645 8.328 64.716 8.4 ;
     RECT  64.645 8.4 64.692 8.424 ;
     RECT  64.645 8.424 64.716 8.496 ;
     RECT  64.645 8.496 64.692 8.52 ;
     RECT  64.645 8.52 64.716 8.592 ;
     RECT  64.645 8.592 64.692 8.616 ;
     RECT  64.645 8.616 64.716 8.688 ;
     RECT  64.645 8.688 64.692 8.712 ;
     RECT  64.645 8.712 64.716 8.784 ;
     RECT  64.645 8.784 64.692 8.808 ;
     RECT  64.645 8.808 64.716 8.88 ;
     RECT  64.645 8.88 64.692 8.904 ;
     RECT  64.645 8.904 64.716 8.976 ;
     RECT  64.645 8.976 64.692 9 ;
     RECT  64.645 9 64.716 9.072 ;
     RECT  64.645 9.072 64.692 9.096 ;
     RECT  64.645 9.096 64.716 9.168 ;
     RECT  64.645 9.168 64.692 9.192 ;
     RECT  64.645 9.192 64.716 9.264 ;
     RECT  64.645 9.264 64.692 9.288 ;
     RECT  64.645 9.288 64.716 9.36 ;
     RECT  64.645 9.36 64.692 9.384 ;
     RECT  64.645 9.384 64.716 9.456 ;
     RECT  64.645 9.456 64.692 9.48 ;
     RECT  64.645 9.48 64.716 9.552 ;
     RECT  64.645 9.552 64.692 9.576 ;
     RECT  64.645 9.576 64.716 9.648 ;
     RECT  64.645 9.648 64.692 9.672 ;
     RECT  64.645 9.672 64.716 9.744 ;
     RECT  64.645 9.744 64.692 9.768 ;
     RECT  64.645 9.768 64.716 9.84 ;
     RECT  64.645 9.84 64.692 9.864 ;
     RECT  64.645 9.864 64.716 9.936 ;
     RECT  64.645 9.936 64.692 9.96 ;
     RECT  64.645 9.96 64.716 10.032 ;
     RECT  64.645 10.032 64.692 10.056 ;
     RECT  64.645 10.056 64.716 10.128 ;
     RECT  64.645 10.128 64.692 10.152 ;
     RECT  64.645 10.152 64.716 10.224 ;
     RECT  64.645 10.224 64.692 10.248 ;
     RECT  64.645 10.248 64.716 10.32 ;
     RECT  64.645 10.32 64.692 10.344 ;
     RECT  64.645 10.344 64.716 10.416 ;
     RECT  64.645 10.416 64.692 10.44 ;
     RECT  64.645 10.44 64.716 10.512 ;
     RECT  64.645 10.512 64.692 10.536 ;
     RECT  64.645 10.536 64.716 10.608 ;
     RECT  64.645 10.608 64.692 10.632 ;
     RECT  64.645 10.632 64.716 10.704 ;
     RECT  64.645 10.704 64.692 10.728 ;
     RECT  64.645 10.728 64.716 10.8 ;
     RECT  64.645 10.8 64.692 10.824 ;
     RECT  64.645 10.824 64.716 10.896 ;
     RECT  64.645 10.896 64.692 10.92 ;
     RECT  64.645 10.92 64.716 10.992 ;
     RECT  64.645 10.992 64.692 11.016 ;
     RECT  64.645 11.016 64.716 11.088 ;
     RECT  64.645 11.088 64.692 11.112 ;
     RECT  64.645 11.112 64.716 11.184 ;
     RECT  64.645 11.184 64.692 11.208 ;
     RECT  64.645 11.208 64.716 11.28 ;
     RECT  64.645 11.28 64.692 11.304 ;
     RECT  64.645 11.304 64.716 11.376 ;
     RECT  64.645 11.376 64.692 11.4 ;
     RECT  64.645 11.4 64.716 11.472 ;
     RECT  64.645 11.472 64.692 11.496 ;
     RECT  64.645 11.496 64.716 11.568 ;
     RECT  64.645 11.568 64.692 11.592 ;
     RECT  64.645 11.592 64.716 11.664 ;
     RECT  64.645 11.664 64.692 11.688 ;
     RECT  64.645 11.688 64.716 11.76 ;
     RECT  64.645 11.76 64.692 11.784 ;
     RECT  64.645 11.784 64.716 11.856 ;
     RECT  64.645 11.856 64.692 11.88 ;
     RECT  64.645 11.88 64.716 11.952 ;
     RECT  64.645 11.952 64.692 11.976 ;
     RECT  64.645 11.976 64.716 12.048 ;
     RECT  64.645 12.048 64.692 12.072 ;
     RECT  64.645 12.072 64.716 12.144 ;
     RECT  64.645 12.144 64.692 12.168 ;
     RECT  64.645 12.168 64.716 12.24 ;
     RECT  64.645 12.24 64.692 12.264 ;
     RECT  64.645 12.264 64.716 12.336 ;
     RECT  64.645 12.336 64.692 12.36 ;
     RECT  64.645 12.36 64.716 12.432 ;
     RECT  64.645 12.432 64.692 12.456 ;
     RECT  64.645 12.456 64.716 12.528 ;
     RECT  64.645 12.528 64.692 12.552 ;
     RECT  64.645 12.552 64.716 12.624 ;
     RECT  64.645 12.624 64.692 12.648 ;
     RECT  64.645 12.648 64.716 12.72 ;
     RECT  64.645 12.72 64.692 12.744 ;
     RECT  64.645 12.744 64.716 12.816 ;
     RECT  64.645 12.816 64.692 12.84 ;
     RECT  64.645 12.84 64.716 12.912 ;
     RECT  64.645 12.912 64.692 12.936 ;
     RECT  64.645 12.936 64.716 13.008 ;
     RECT  64.645 13.008 64.692 13.032 ;
     RECT  64.645 13.032 64.716 13.104 ;
     RECT  64.645 13.104 64.692 13.128 ;
     RECT  64.645 13.128 64.716 13.2 ;
     RECT  64.645 13.2 64.692 13.224 ;
     RECT  64.645 13.224 64.716 13.296 ;
     RECT  64.645 13.296 64.692 13.32 ;
     RECT  64.645 13.32 64.716 13.392 ;
     RECT  64.645 13.392 64.692 13.416 ;
     RECT  64.645 13.416 64.716 13.488 ;
     RECT  64.645 13.488 64.692 13.512 ;
     RECT  64.645 13.512 64.716 13.584 ;
     RECT  64.645 13.584 64.692 13.608 ;
     RECT  64.645 13.608 64.716 13.68 ;
     RECT  64.645 13.68 64.692 13.704 ;
     RECT  64.645 13.704 64.716 13.776 ;
     RECT  64.645 13.776 64.692 13.8 ;
     RECT  64.645 13.8 64.716 13.872 ;
     RECT  64.645 13.872 64.692 13.896 ;
     RECT  64.645 13.896 64.716 13.968 ;
     RECT  64.645 13.968 64.692 13.992 ;
     RECT  64.645 13.992 64.716 14.064 ;
     RECT  64.645 14.064 64.692 14.088 ;
     RECT  64.645 14.088 64.716 14.16 ;
     RECT  64.645 14.16 64.692 14.184 ;
     RECT  64.645 14.184 64.716 14.256 ;
     RECT  64.645 14.256 64.692 14.28 ;
     RECT  64.645 14.28 64.716 14.352 ;
     RECT  64.645 14.352 64.692 14.376 ;
     RECT  64.645 14.376 64.716 14.448 ;
     RECT  64.645 14.448 64.692 14.472 ;
     RECT  64.645 14.472 64.716 14.544 ;
     RECT  64.645 14.544 64.692 14.568 ;
     RECT  64.645 14.568 64.716 14.64 ;
     RECT  64.645 14.64 64.692 14.664 ;
     RECT  64.645 14.664 64.716 14.736 ;
     RECT  64.645 14.736 64.692 14.76 ;
     RECT  64.645 14.76 64.716 14.832 ;
     RECT  64.645 14.832 64.692 14.856 ;
     RECT  64.645 14.856 64.716 14.928 ;
     RECT  64.645 14.928 64.692 14.952 ;
     RECT  64.645 14.952 64.716 15.024 ;
     RECT  64.645 15.024 64.692 15.048 ;
     RECT  64.645 15.048 64.716 15.12 ;
     RECT  64.645 15.12 64.692 15.144 ;
     RECT  64.645 15.144 64.716 15.216 ;
     RECT  64.645 15.216 64.692 15.24 ;
     RECT  64.645 15.24 64.716 15.312 ;
     RECT  64.645 15.312 64.692 15.336 ;
     RECT  64.645 15.336 64.716 15.408 ;
     RECT  64.645 15.408 64.692 15.432 ;
     RECT  64.645 15.432 64.716 15.504 ;
     RECT  64.645 15.504 64.692 15.528 ;
     RECT  64.645 15.528 64.716 15.6 ;
     RECT  64.645 15.6 64.692 15.624 ;
     RECT  64.645 15.624 64.716 15.696 ;
     RECT  64.645 15.696 64.692 15.72 ;
     RECT  64.645 15.72 64.716 15.792 ;
     RECT  64.645 15.792 64.692 15.816 ;
     RECT  64.645 15.816 64.716 15.888 ;
     RECT  64.645 15.888 64.692 15.912 ;
     RECT  64.645 15.912 64.716 15.984 ;
     RECT  64.645 15.984 64.692 16.008 ;
     RECT  64.645 16.008 64.716 16.08 ;
     RECT  64.645 16.08 64.692 16.104 ;
     RECT  64.645 16.104 64.716 16.176 ;
     RECT  64.645 16.176 64.692 16.2 ;
     RECT  64.645 16.2 64.716 16.272 ;
     RECT  64.645 16.272 64.692 16.296 ;
     RECT  64.645 16.296 64.716 16.368 ;
     RECT  64.645 16.368 64.692 16.392 ;
     RECT  64.645 16.392 64.716 16.464 ;
     RECT  64.645 16.464 64.692 16.488 ;
     RECT  64.645 16.488 64.716 16.56 ;
     RECT  64.645 16.56 64.692 16.584 ;
     RECT  64.645 16.584 64.716 16.656 ;
     RECT  64.645 16.656 64.692 16.68 ;
     RECT  64.645 16.68 64.716 16.752 ;
     RECT  64.645 16.752 64.692 16.776 ;
     RECT  64.645 16.776 64.716 16.848 ;
     RECT  64.645 16.848 64.692 16.872 ;
     RECT  64.645 16.872 64.716 16.944 ;
     RECT  64.645 16.944 64.692 16.968 ;
     RECT  64.645 16.968 64.716 17.04 ;
     RECT  64.645 17.04 64.692 17.064 ;
     RECT  64.645 17.064 64.716 17.136 ;
     RECT  64.645 17.136 64.692 17.16 ;
     RECT  64.645 17.16 64.716 17.232 ;
     RECT  64.645 17.232 64.692 17.256 ;
     RECT  64.645 17.256 64.716 17.328 ;
     RECT  64.645 17.328 64.692 17.352 ;
     RECT  64.645 17.352 64.716 17.424 ;
     RECT  64.645 17.424 64.692 17.448 ;
     RECT  64.645 17.448 64.716 17.52 ;
     RECT  64.645 17.52 64.692 17.544 ;
     RECT  64.645 17.544 64.716 17.616 ;
     RECT  64.645 17.616 64.692 17.64 ;
     RECT  64.645 17.64 64.716 17.712 ;
     RECT  64.645 17.712 64.692 17.736 ;
     RECT  64.645 17.736 64.716 17.808 ;
     RECT  64.645 17.808 64.692 17.832 ;
     RECT  64.645 17.832 64.716 17.904 ;
     RECT  64.645 17.904 64.692 17.928 ;
     RECT  64.645 17.928 64.716 18 ;
     RECT  64.645 18 64.692 18.024 ;
     RECT  64.645 18.024 64.716 18.096 ;
     RECT  64.645 18.096 64.692 18.12 ;
     RECT  64.645 18.12 64.716 18.192 ;
     RECT  64.645 18.192 64.692 18.216 ;
     RECT  64.645 18.216 64.716 18.288 ;
     RECT  64.645 18.288 64.692 18.312 ;
     RECT  64.645 18.312 64.716 18.384 ;
     RECT  64.645 18.384 64.692 18.408 ;
     RECT  64.645 18.408 64.716 18.48 ;
     RECT  64.645 18.48 64.692 18.504 ;
     RECT  64.645 18.504 64.716 18.576 ;
     RECT  64.645 18.576 64.692 18.6 ;
     RECT  64.645 18.6 64.716 18.672 ;
     RECT  64.645 18.672 64.692 18.696 ;
     RECT  64.645 18.696 64.716 18.768 ;
     RECT  64.645 18.768 64.692 18.792 ;
     RECT  64.645 18.792 64.716 18.864 ;
     RECT  64.645 18.864 64.692 18.888 ;
     RECT  64.645 18.888 64.716 18.96 ;
     RECT  64.645 18.96 64.692 18.984 ;
     RECT  64.645 18.984 64.716 19.056 ;
     RECT  64.645 19.056 64.692 19.08 ;
     RECT  64.645 19.08 64.716 19.152 ;
     RECT  64.645 19.152 64.692 19.176 ;
     RECT  64.716 9.504 64.757 9.528 ;
     RECT  64.716 12.192 64.757 12.216 ;
    LAYER M5 ;
     RECT  2.4 2.137 2.52 2.151 ;
     RECT  5.1 2.137 5.22 2.151 ;
     RECT  7.8 2.137 7.92 2.151 ;
     RECT  10.5 2.137 10.62 2.151 ;
     RECT  13.2 2.137 13.32 2.151 ;
     RECT  15.9 2.137 16.02 2.151 ;
     RECT  18.6 2.137 18.72 2.151 ;
     RECT  21.3 2.137 21.42 2.151 ;
     RECT  24 2.137 24.12 2.151 ;
     RECT  26.7 2.137 26.82 2.151 ;
     RECT  29.4 2.137 29.52 2.151 ;
     RECT  32.1 2.137 32.22 2.151 ;
     RECT  34.8 2.137 34.92 2.151 ;
     RECT  37.5 2.137 37.62 2.151 ;
     RECT  40.2 2.137 40.32 2.151 ;
     RECT  42.9 2.137 43.02 2.151 ;
     RECT  45.6 2.137 45.72 2.151 ;
     RECT  48.3 2.137 48.42 2.151 ;
     RECT  51 2.137 51.12 2.151 ;
     RECT  53.7 2.137 53.82 2.151 ;
     RECT  56.4 2.137 56.52 2.151 ;
     RECT  59.1 2.137 59.22 2.151 ;
     RECT  61.8 2.137 61.92 2.151 ;
     RECT  56.4 2.151 56.712 7.909 ;
     RECT  55.824 7.909 56.712 8.917 ;
     RECT  53.7 2.151 54.012 8.965 ;
     RECT  24 2.151 24.312 9.205 ;
     RECT  55.344 8.917 56.712 9.251 ;
     RECT  2.4 2.151 2.712 9.301 ;
     RECT  23.904 9.205 24.312 9.347 ;
     RECT  45.6 2.151 45.912 9.541 ;
     RECT  53.568 8.965 54.12 9.731 ;
     RECT  56.064 9.251 56.712 9.829 ;
     RECT  53.568 9.731 54.012 9.875 ;
     RECT  56.064 9.829 57 10.595 ;
     RECT  56.4 10.595 57 11.459 ;
     RECT  2.4 9.301 3.432 11.507 ;
     RECT  24 9.347 24.312 12.805 ;
     RECT  32.1 2.151 32.412 13.093 ;
     RECT  45.6 9.541 46.44 13.139 ;
     RECT  23.904 12.805 24.312 13.667 ;
     RECT  56.4 11.459 56.712 13.765 ;
     RECT  57.84 13.477 57.864 13.765 ;
     RECT  22.8 14.437 22.824 14.579 ;
     RECT  56.4 13.765 57.864 15.683 ;
     RECT  59.1 2.151 59.412 17.077 ;
     RECT  56.4 15.683 57.096 17.605 ;
     RECT  53.7 9.875 54.012 17.989 ;
     RECT  58.992 17.077 59.412 18.133 ;
     RECT  55.92 17.605 57.096 18.179 ;
     RECT  58.656 18.133 59.412 18.803 ;
     RECT  60.576 17.989 60.6 18.803 ;
     RECT  55.92 18.179 56.712 18.995 ;
     RECT  14.832 20.629 14.856 21.347 ;
     RECT  22.8 21.157 22.824 21.347 ;
     RECT  24 13.667 24.312 21.973 ;
     RECT  23.904 21.973 24.312 22.115 ;
     RECT  15.9 2.151 16.212 23.077 ;
     RECT  14.928 23.077 16.212 23.315 ;
     RECT  22.8 23.077 22.824 23.411 ;
     RECT  53.7 17.989 54.552 27.635 ;
     RECT  31.68 13.093 32.412 27.781 ;
     RECT  2.4 11.507 2.712 27.819 ;
     RECT  5.1 2.151 5.412 27.819 ;
     RECT  7.8 2.151 8.112 27.819 ;
     RECT  10.5 2.151 10.812 27.819 ;
     RECT  13.2 2.151 13.512 27.819 ;
     RECT  15.9 23.315 16.212 27.819 ;
     RECT  18.6 2.151 18.912 27.819 ;
     RECT  21.3 2.151 21.612 27.819 ;
     RECT  24 22.115 24.312 27.819 ;
     RECT  26.7 2.151 27.012 27.819 ;
     RECT  29.4 2.151 29.712 27.819 ;
     RECT  34.8 2.151 35.112 27.819 ;
     RECT  37.5 2.151 37.812 27.819 ;
     RECT  40.2 2.151 40.512 27.819 ;
     RECT  42.9 2.151 43.212 27.819 ;
     RECT  45.6 13.139 45.912 27.819 ;
     RECT  48.3 2.151 48.612 27.819 ;
     RECT  51 2.151 51.312 27.819 ;
     RECT  53.7 27.635 54.012 27.819 ;
     RECT  56.4 18.995 56.712 27.819 ;
     RECT  59.1 18.803 59.412 27.819 ;
     RECT  61.8 2.151 62.112 27.819 ;
     RECT  2.592 27.819 2.712 27.833 ;
     RECT  5.292 27.819 5.412 27.833 ;
     RECT  7.992 27.819 8.112 27.833 ;
     RECT  10.692 27.819 10.812 27.833 ;
     RECT  13.392 27.819 13.512 27.833 ;
     RECT  16.092 27.819 16.212 27.833 ;
     RECT  18.792 27.819 18.912 27.833 ;
     RECT  21.492 27.819 21.612 27.833 ;
     RECT  24.192 27.819 24.312 27.833 ;
     RECT  26.892 27.819 27.012 27.833 ;
     RECT  29.592 27.819 29.712 27.833 ;
     RECT  31.536 27.781 32.412 27.833 ;
     RECT  34.992 27.819 35.112 27.833 ;
     RECT  37.692 27.819 37.812 27.833 ;
     RECT  40.392 27.819 40.512 27.833 ;
     RECT  43.092 27.819 43.212 27.833 ;
     RECT  45.792 27.819 45.912 27.833 ;
     RECT  48.492 27.819 48.612 27.833 ;
     RECT  51.192 27.819 51.312 27.833 ;
     RECT  53.892 27.819 54.012 27.833 ;
     RECT  56.592 27.819 56.712 27.833 ;
     RECT  59.292 27.819 59.412 27.833 ;
     RECT  61.992 27.819 62.112 27.833 ;
     RECT  31.536 27.833 31.704 29.699 ;
     RECT  31.68 29.699 31.704 30.131 ;
     RECT  54.012 8.917 55.344 8.965 ;
     RECT  54.12 8.965 55.344 9.251 ;
     RECT  56.712 13.477 57.84 13.765 ;
     RECT  57.864 13.477 59.1 15.683 ;
     RECT  23.904 13.667 24 14.437 ;
     RECT  21.612 14.437 22.8 14.579 ;
     RECT  22.824 14.437 24 14.579 ;
     RECT  58.992 15.683 59.1 17.077 ;
     RECT  54.552 17.989 55.92 18.995 ;
     RECT  59.412 17.989 60.576 18.803 ;
     RECT  60.6 17.989 61.8 18.803 ;
     RECT  13.512 20.629 14.832 21.347 ;
     RECT  14.856 20.629 15.9 21.347 ;
     RECT  21.612 21.157 22.8 21.347 ;
     RECT  22.824 21.157 24 21.347 ;
     RECT  23.904 21.347 24 21.973 ;
     RECT  23.904 22.115 24 23.077 ;
     RECT  13.512 23.077 14.928 23.315 ;
     RECT  21.612 23.077 22.8 23.411 ;
     RECT  22.824 23.077 24 23.411 ;
  END
END qfd_rlyh_128_EW_65x30
END LIBRARY
